VERSION 5.7 ;
  NOWIREEXTENSIONATPIN ON ;
  DIVIDERCHAR "/" ;
  BUSBITCHARS "[]" ;
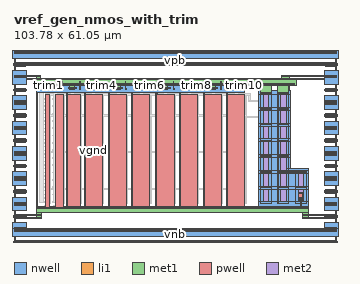
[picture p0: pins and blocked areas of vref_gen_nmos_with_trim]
MACRO vref_gen_nmos_with_trim
  CLASS BLOCK ;
  FOREIGN vref_gen_nmos_with_trim ;
  ORIGIN 0.000 0.000 ;
  SIZE 103.780 BY 61.050 ;
  PIN vpb
    ANTENNADIFFAREA 17.642599 ;
    PORT
      LAYER nwell ;
        RECT -0.330 58.865 104.110 61.465 ;
      LAYER li1 ;
        RECT 0.000 60.965 103.780 61.135 ;
      LAYER met1 ;
        RECT 0.000 60.935 103.780 61.165 ;
    END
    PORT
      LAYER nwell ;
        RECT 99.610 50.725 104.110 55.095 ;
      LAYER li1 ;
        RECT 99.940 52.825 103.780 52.995 ;
      LAYER met1 ;
        RECT 99.940 52.795 103.780 53.025 ;
    END
    PORT
      LAYER nwell ;
        RECT 99.610 42.585 104.110 46.955 ;
      LAYER li1 ;
        RECT 99.940 44.685 103.780 44.855 ;
      LAYER met1 ;
        RECT 99.940 44.655 103.780 44.885 ;
    END
    PORT
      LAYER nwell ;
        RECT 99.610 34.445 104.110 38.815 ;
      LAYER li1 ;
        RECT 99.940 36.545 103.780 36.715 ;
      LAYER met1 ;
        RECT 99.940 36.515 103.780 36.745 ;
    END
    PORT
      LAYER nwell ;
        RECT -0.330 50.725 4.170 55.095 ;
      LAYER li1 ;
        RECT 0.000 52.825 3.840 52.995 ;
      LAYER met1 ;
        RECT 0.000 52.795 3.840 53.025 ;
    END
    PORT
      LAYER nwell ;
        RECT -0.330 42.585 4.170 46.955 ;
      LAYER li1 ;
        RECT 0.000 44.685 3.840 44.855 ;
      LAYER met1 ;
        RECT 0.000 44.655 3.840 44.885 ;
    END
    PORT
      LAYER nwell ;
        RECT -0.330 34.445 4.170 38.815 ;
      LAYER li1 ;
        RECT 0.000 36.545 3.840 36.715 ;
      LAYER met1 ;
        RECT 0.000 36.515 3.840 36.745 ;
    END
    PORT
      LAYER nwell ;
        RECT -0.330 26.305 4.170 30.675 ;
      LAYER li1 ;
        RECT 0.000 28.405 3.840 28.575 ;
      LAYER met1 ;
        RECT 0.000 28.375 3.840 28.605 ;
    END
    PORT
      LAYER nwell ;
        RECT -0.330 18.165 4.170 22.535 ;
      LAYER li1 ;
        RECT 0.000 20.265 3.840 20.435 ;
      LAYER met1 ;
        RECT 0.000 20.235 3.840 20.465 ;
    END
    PORT
      LAYER nwell ;
        RECT -0.330 4.485 4.170 6.255 ;
        RECT 99.610 4.485 104.110 6.255 ;
        RECT -0.330 1.885 104.110 4.485 ;
      LAYER li1 ;
        RECT 0.000 3.985 103.780 4.155 ;
      LAYER met1 ;
        RECT 0.000 3.955 103.780 4.185 ;
    END
    PORT
      LAYER nwell ;
        RECT -0.330 10.025 4.170 14.395 ;
      LAYER li1 ;
        RECT 0.000 12.125 3.840 12.295 ;
      LAYER met1 ;
        RECT 0.000 12.095 3.840 12.325 ;
    END
    PORT
      LAYER nwell ;
        RECT 99.610 18.165 104.110 22.535 ;
      LAYER li1 ;
        RECT 99.940 20.265 103.780 20.435 ;
      LAYER met1 ;
        RECT 99.940 20.235 103.780 20.465 ;
    END
    PORT
      LAYER nwell ;
        RECT 99.610 26.305 104.110 30.675 ;
      LAYER li1 ;
        RECT 99.940 28.405 103.780 28.575 ;
      LAYER met1 ;
        RECT 99.940 28.375 103.780 28.605 ;
    END
    PORT
      LAYER nwell ;
        RECT 99.610 10.025 104.110 14.395 ;
      LAYER li1 ;
        RECT 99.940 12.125 103.780 12.295 ;
      LAYER met1 ;
        RECT 99.940 12.095 103.780 12.325 ;
    END
  END vpb
  PIN vnb
    ANTENNADIFFAREA 0.652800 ;
    PORT
      LAYER pwell ;
        RECT 99.810 48.625 103.910 49.055 ;
      LAYER li1 ;
        RECT 99.940 48.755 103.780 48.925 ;
      LAYER met1 ;
        RECT 99.940 48.725 103.780 48.955 ;
    END
    PORT
      LAYER pwell ;
        RECT -0.130 56.765 103.910 57.195 ;
      LAYER li1 ;
        RECT 0.000 56.895 103.780 57.065 ;
      LAYER met1 ;
        RECT 0.000 56.865 103.780 57.095 ;
    END
    PORT
      LAYER pwell ;
        RECT 99.810 32.345 103.910 32.775 ;
      LAYER li1 ;
        RECT 99.940 32.475 103.780 32.645 ;
      LAYER met1 ;
        RECT 99.940 32.445 103.780 32.675 ;
    END
    PORT
      LAYER pwell ;
        RECT 99.810 40.485 103.910 40.915 ;
      LAYER li1 ;
        RECT 99.940 40.615 103.780 40.785 ;
      LAYER met1 ;
        RECT 99.940 40.585 103.780 40.815 ;
    END
    PORT
      LAYER pwell ;
        RECT -0.130 48.625 3.970 49.055 ;
      LAYER li1 ;
        RECT 0.000 48.755 3.840 48.925 ;
      LAYER met1 ;
        RECT 0.000 48.725 3.840 48.955 ;
    END
    PORT
      LAYER pwell ;
        RECT -0.130 40.485 3.970 40.915 ;
      LAYER li1 ;
        RECT 0.000 40.615 3.840 40.785 ;
      LAYER met1 ;
        RECT 0.000 40.585 3.840 40.815 ;
    END
    PORT
      LAYER pwell ;
        RECT -0.130 32.345 3.970 32.775 ;
      LAYER li1 ;
        RECT 0.000 32.475 3.840 32.645 ;
      LAYER met1 ;
        RECT 0.000 32.445 3.840 32.675 ;
    END
    PORT
      LAYER pwell ;
        RECT -0.130 24.205 3.970 24.635 ;
      LAYER li1 ;
        RECT 0.000 24.335 3.840 24.505 ;
      LAYER met1 ;
        RECT 0.000 24.305 3.840 24.535 ;
    END
    PORT
      LAYER pwell ;
        RECT -0.130 16.065 3.970 16.495 ;
      LAYER li1 ;
        RECT 0.000 16.195 3.840 16.365 ;
      LAYER met1 ;
        RECT 0.000 16.165 3.840 16.395 ;
    END
    PORT
      LAYER pwell ;
        RECT -0.130 -0.215 103.910 0.215 ;
      LAYER li1 ;
        RECT 0.000 -0.085 103.780 0.085 ;
      LAYER met1 ;
        RECT 0.000 -0.115 103.780 0.115 ;
    END
    PORT
      LAYER pwell ;
        RECT -0.130 7.925 3.970 8.355 ;
      LAYER li1 ;
        RECT 0.000 8.055 3.840 8.225 ;
      LAYER met1 ;
        RECT 0.000 8.025 3.840 8.255 ;
    END
    PORT
      LAYER pwell ;
        RECT 99.810 24.205 103.910 24.635 ;
      LAYER li1 ;
        RECT 99.940 24.335 103.780 24.505 ;
      LAYER met1 ;
        RECT 99.940 24.305 103.780 24.535 ;
    END
    PORT
      LAYER pwell ;
        RECT 99.810 16.065 103.910 16.495 ;
      LAYER li1 ;
        RECT 99.940 16.195 103.780 16.365 ;
      LAYER met1 ;
        RECT 99.940 16.165 103.780 16.395 ;
    END
    PORT
      LAYER pwell ;
        RECT 99.810 7.925 103.910 8.355 ;
      LAYER li1 ;
        RECT 99.940 8.055 103.780 8.225 ;
      LAYER met1 ;
        RECT 99.940 8.025 103.780 8.255 ;
    END
  END vnb
  PIN vpwr
    PORT
      LAYER met1 ;
        RECT 0.000 60.425 103.780 60.795 ;
    END
    PORT
      LAYER nwell ;
        RECT 7.180 48.170 74.045 51.165 ;
        RECT 78.610 47.355 88.880 48.785 ;
        RECT 78.610 43.250 80.040 47.355 ;
        RECT 81.900 43.250 85.590 47.355 ;
        RECT 87.450 43.250 88.880 47.355 ;
        RECT 78.610 42.300 88.880 43.250 ;
        RECT 78.610 38.195 80.040 42.300 ;
        RECT 81.900 38.195 85.590 42.300 ;
        RECT 87.450 38.195 88.880 42.300 ;
        RECT 78.610 37.245 88.880 38.195 ;
        RECT 78.610 33.140 80.040 37.245 ;
        RECT 81.900 33.140 85.590 37.245 ;
        RECT 87.450 33.140 88.880 37.245 ;
        RECT 78.610 32.190 88.880 33.140 ;
        RECT 78.610 28.085 80.040 32.190 ;
        RECT 81.900 28.085 85.590 32.190 ;
        RECT 87.450 28.085 88.880 32.190 ;
        RECT 78.610 27.135 88.880 28.085 ;
        RECT 78.610 23.030 80.040 27.135 ;
        RECT 81.900 23.030 85.590 27.135 ;
        RECT 87.450 23.510 88.880 27.135 ;
        RECT 87.450 23.030 94.550 23.510 ;
        RECT 78.610 22.080 94.550 23.030 ;
        RECT 78.610 17.975 80.040 22.080 ;
        RECT 81.900 17.975 85.590 22.080 ;
        RECT 87.450 17.975 91.260 22.080 ;
        RECT 93.120 17.975 94.550 22.080 ;
        RECT 78.610 17.025 94.550 17.975 ;
        RECT 78.610 12.920 80.040 17.025 ;
        RECT 81.900 12.920 85.590 17.025 ;
        RECT 87.450 12.920 91.260 17.025 ;
        RECT 93.120 12.920 94.550 17.025 ;
        RECT 78.610 11.490 94.550 12.920 ;
      LAYER li1 ;
        RECT 7.700 50.465 90.045 50.795 ;
        RECT 7.490 49.430 10.200 49.600 ;
        RECT 11.975 49.430 14.685 49.600 ;
        RECT 17.435 49.430 20.145 49.600 ;
        RECT 24.460 49.430 27.170 49.600 ;
        RECT 32.195 49.430 34.905 49.600 ;
        RECT 39.750 49.430 42.460 49.600 ;
        RECT 47.560 49.430 50.270 49.600 ;
        RECT 55.070 49.430 57.780 49.600 ;
        RECT 62.745 49.430 65.455 49.600 ;
        RECT 70.255 49.430 72.965 49.600 ;
        RECT 79.135 47.745 82.795 47.915 ;
        RECT 79.135 42.860 79.305 47.745 ;
        RECT 82.625 42.860 82.795 47.745 ;
        RECT 79.135 42.690 82.795 42.860 ;
        RECT 79.135 37.805 79.305 42.690 ;
        RECT 82.625 37.805 82.795 42.690 ;
        RECT 79.135 37.635 82.795 37.805 ;
        RECT 79.135 32.750 79.305 37.635 ;
        RECT 82.625 32.750 82.795 37.635 ;
        RECT 79.135 32.580 82.795 32.750 ;
        RECT 79.135 27.695 79.305 32.580 ;
        RECT 82.625 27.695 82.795 32.580 ;
        RECT 79.135 27.525 82.795 27.695 ;
        RECT 79.135 22.640 79.305 27.525 ;
        RECT 82.625 22.640 82.795 27.525 ;
        RECT 79.135 22.470 82.795 22.640 ;
        RECT 79.135 17.585 79.305 22.470 ;
        RECT 82.625 17.585 82.795 22.470 ;
        RECT 79.135 17.415 82.795 17.585 ;
        RECT 79.135 12.505 79.305 17.415 ;
        RECT 82.625 12.505 82.795 17.415 ;
        RECT 79.135 12.335 82.795 12.505 ;
        RECT 84.685 47.745 88.345 47.915 ;
        RECT 84.685 42.860 84.855 47.745 ;
        RECT 88.175 42.860 88.345 47.745 ;
        RECT 84.685 42.690 88.345 42.860 ;
        RECT 84.685 37.805 84.855 42.690 ;
        RECT 88.175 37.805 88.345 42.690 ;
        RECT 84.685 37.635 88.345 37.805 ;
        RECT 84.685 32.750 84.855 37.635 ;
        RECT 88.175 32.750 88.345 37.635 ;
        RECT 84.685 32.580 88.345 32.750 ;
        RECT 84.685 27.695 84.855 32.580 ;
        RECT 88.175 27.695 88.345 32.580 ;
        RECT 84.685 27.525 88.345 27.695 ;
        RECT 84.685 22.640 84.855 27.525 ;
        RECT 88.175 22.640 88.345 27.525 ;
        RECT 84.685 22.470 94.015 22.640 ;
        RECT 84.685 17.585 84.855 22.470 ;
        RECT 88.175 17.585 88.345 22.470 ;
        RECT 84.685 17.415 88.345 17.585 ;
        RECT 84.685 12.505 84.855 17.415 ;
        RECT 88.175 12.505 88.345 17.415 ;
        RECT 84.685 12.335 88.345 12.505 ;
        RECT 90.355 17.585 90.525 22.470 ;
        RECT 93.845 17.585 94.015 22.470 ;
        RECT 90.355 17.415 94.015 17.585 ;
        RECT 90.355 12.505 90.525 17.415 ;
        RECT 93.845 12.505 94.015 17.415 ;
        RECT 90.355 12.335 94.015 12.505 ;
      LAYER met1 ;
        RECT 0.000 53.165 8.370 53.535 ;
        RECT 7.180 52.655 8.370 53.165 ;
        RECT 86.065 53.165 103.780 53.535 ;
        RECT 86.065 52.655 88.435 53.165 ;
        RECT 0.000 52.285 103.780 52.655 ;
        RECT 7.180 50.295 90.730 52.285 ;
        RECT 8.030 48.965 9.400 50.295 ;
        RECT 12.520 48.965 13.890 50.295 ;
        RECT 17.980 48.965 19.350 50.295 ;
        RECT 25.005 48.965 26.375 50.295 ;
        RECT 32.740 48.965 34.110 50.295 ;
        RECT 40.295 48.965 41.665 50.295 ;
        RECT 48.105 48.965 49.475 50.295 ;
        RECT 55.615 48.965 56.985 50.295 ;
        RECT 63.290 48.965 64.660 50.295 ;
        RECT 70.800 48.965 72.170 50.295 ;
        RECT 79.265 47.715 82.795 50.295 ;
        RECT 84.815 47.715 88.345 50.295 ;
        RECT 90.475 22.670 93.675 22.700 ;
        RECT 90.335 22.440 93.865 22.670 ;
      LAYER met2 ;
        RECT 79.080 12.280 82.830 51.015 ;
        RECT 84.630 12.280 88.380 51.015 ;
        RECT 90.300 12.280 94.050 23.395 ;
    END
    PORT
      LAYER met1 ;
        RECT 99.940 44.145 103.780 44.515 ;
    END
    PORT
      LAYER met1 ;
        RECT 99.940 36.005 103.780 36.375 ;
    END
    PORT
      LAYER met1 ;
        RECT 99.940 36.885 103.780 37.255 ;
    END
    PORT
      LAYER met1 ;
        RECT 99.940 45.025 103.780 45.395 ;
    END
    PORT
      LAYER met1 ;
        RECT 0.000 44.145 3.840 44.515 ;
    END
    PORT
      LAYER met1 ;
        RECT 0.000 36.005 3.840 36.375 ;
    END
    PORT
      LAYER met1 ;
        RECT 0.000 45.025 3.840 45.395 ;
    END
    PORT
      LAYER met1 ;
        RECT 0.000 36.885 3.840 37.255 ;
    END
    PORT
      LAYER met1 ;
        RECT 0.000 27.865 3.840 28.235 ;
    END
    PORT
      LAYER met1 ;
        RECT 0.000 19.725 3.840 20.095 ;
    END
    PORT
      LAYER met1 ;
        RECT 0.000 28.745 3.840 29.115 ;
    END
    PORT
      LAYER met1 ;
        RECT 0.000 20.605 3.840 20.975 ;
    END
    PORT
      LAYER met1 ;
        RECT 0.000 3.445 103.780 3.815 ;
    END
    PORT
      LAYER met1 ;
        RECT 0.000 4.325 3.840 4.695 ;
    END
    PORT
      LAYER met1 ;
        RECT 0.000 11.585 3.840 11.955 ;
    END
    PORT
      LAYER met1 ;
        RECT 0.000 12.465 3.840 12.835 ;
    END
    PORT
      LAYER met1 ;
        RECT 99.940 20.605 103.780 20.975 ;
    END
    PORT
      LAYER met1 ;
        RECT 99.940 19.725 103.780 20.095 ;
    END
    PORT
      LAYER met1 ;
        RECT 99.940 28.745 103.780 29.115 ;
    END
    PORT
      LAYER met1 ;
        RECT 99.940 27.865 103.780 28.235 ;
    END
    PORT
      LAYER met1 ;
        RECT 99.940 11.585 103.780 11.955 ;
    END
    PORT
      LAYER met1 ;
        RECT 99.940 12.465 103.780 12.835 ;
    END
    PORT
      LAYER met1 ;
        RECT 99.940 4.325 103.780 4.695 ;
    END
  END vpwr
  PIN vgnd
    PORT
      LAYER met1 ;
        RECT 99.940 48.215 103.780 48.585 ;
    END
    PORT
      LAYER met1 ;
        RECT 0.000 57.235 103.780 57.605 ;
    END
    PORT
      LAYER met1 ;
        RECT 99.940 49.095 103.780 49.465 ;
    END
    PORT
      LAYER met1 ;
        RECT 99.940 56.355 103.780 56.725 ;
    END
    PORT
      LAYER met1 ;
        RECT 99.940 31.935 103.780 32.305 ;
    END
    PORT
      LAYER met1 ;
        RECT 99.940 40.955 103.780 41.325 ;
    END
    PORT
      LAYER met1 ;
        RECT 99.940 32.815 103.780 33.185 ;
    END
    PORT
      LAYER met1 ;
        RECT 99.940 40.075 103.780 40.445 ;
    END
    PORT
      LAYER met1 ;
        RECT 0.000 56.355 3.840 56.725 ;
    END
    PORT
      LAYER met1 ;
        RECT 0.000 49.095 3.840 49.465 ;
    END
    PORT
      LAYER met1 ;
        RECT 0.000 48.215 3.840 48.585 ;
    END
    PORT
      LAYER met1 ;
        RECT 0.000 40.075 3.840 40.445 ;
    END
    PORT
      LAYER met1 ;
        RECT 0.000 40.955 3.840 41.325 ;
    END
    PORT
      LAYER met1 ;
        RECT 0.000 32.815 3.840 33.185 ;
    END
    PORT
      LAYER met1 ;
        RECT 0.000 31.935 3.840 32.305 ;
    END
    PORT
      LAYER met1 ;
        RECT 0.000 23.795 3.840 24.165 ;
    END
    PORT
      LAYER met1 ;
        RECT 0.000 24.675 3.840 25.045 ;
    END
    PORT
      LAYER met1 ;
        RECT 0.000 16.535 3.840 16.905 ;
    END
    PORT
      LAYER met1 ;
        RECT 0.000 15.655 3.840 16.025 ;
    END
    PORT
      LAYER met1 ;
        RECT 0.000 0.255 103.780 0.625 ;
    END
    PORT
      LAYER pwell ;
        RECT 7.175 11.115 7.605 47.580 ;
        RECT 16.790 47.410 17.220 47.580 ;
        RECT 22.515 47.410 22.945 47.580 ;
        RECT 30.250 47.410 30.680 47.580 ;
        RECT 37.805 47.410 38.235 47.580 ;
        RECT 45.615 47.410 46.045 47.580 ;
        RECT 53.125 47.410 53.555 47.580 ;
        RECT 60.800 47.410 61.230 47.580 ;
        RECT 68.310 47.410 68.740 47.580 ;
        RECT 10.160 11.115 11.420 47.410 ;
        RECT 13.345 11.115 15.905 47.410 ;
        RECT 16.790 11.115 21.365 47.410 ;
        RECT 22.515 11.115 28.390 47.410 ;
        RECT 30.250 11.115 36.125 47.410 ;
        RECT 37.805 11.115 43.680 47.410 ;
        RECT 45.615 11.115 51.490 47.410 ;
        RECT 53.125 11.115 59.000 47.410 ;
        RECT 60.800 11.115 66.675 47.410 ;
        RECT 68.310 11.115 74.185 47.410 ;
        RECT 91.560 13.220 92.820 16.005 ;
        RECT 7.170 10.685 94.330 11.115 ;
      LAYER li1 ;
        RECT 7.305 11.065 7.475 47.410 ;
        RECT 16.920 11.065 17.090 47.410 ;
        RECT 22.645 11.065 22.815 47.410 ;
        RECT 30.380 11.065 30.550 47.410 ;
        RECT 37.935 11.065 38.105 47.410 ;
        RECT 45.745 11.065 45.915 47.410 ;
        RECT 53.255 11.065 53.425 47.410 ;
        RECT 60.930 11.065 61.100 47.410 ;
        RECT 68.440 11.065 68.610 47.410 ;
        RECT 91.700 15.665 93.120 15.835 ;
        RECT 92.950 14.275 93.120 15.665 ;
        RECT 91.700 14.105 93.120 14.275 ;
        RECT 92.095 13.600 92.265 14.105 ;
        RECT 91.465 13.270 92.995 13.600 ;
        RECT 7.305 10.985 94.325 11.065 ;
        RECT 7.305 10.815 94.385 10.985 ;
        RECT 7.305 10.735 94.325 10.815 ;
      LAYER met1 ;
        RECT 92.065 13.290 92.355 13.580 ;
        RECT 92.140 11.280 92.280 13.290 ;
        RECT 7.180 9.550 94.590 11.280 ;
        RECT 7.180 8.765 8.920 9.550 ;
        RECT 0.000 8.395 8.920 8.765 ;
        RECT 7.180 7.885 8.920 8.395 ;
        RECT 0.000 7.515 8.920 7.885 ;
        RECT 92.850 8.765 94.590 9.550 ;
        RECT 92.850 8.395 103.780 8.765 ;
        RECT 92.850 7.885 94.590 8.395 ;
        RECT 92.850 7.515 103.780 7.885 ;
    END
    PORT
      LAYER met1 ;
        RECT 99.940 24.675 103.780 25.045 ;
    END
    PORT
      LAYER met1 ;
        RECT 99.940 23.795 103.780 24.165 ;
    END
    PORT
      LAYER met1 ;
        RECT 99.940 16.535 103.780 16.905 ;
    END
    PORT
      LAYER met1 ;
        RECT 99.940 15.655 103.780 16.025 ;
    END
  END vgnd
  PIN trim9
    ANTENNAGATEAREA 1.500000 ;
    PORT
      LAYER li1 ;
        RECT 66.300 48.980 66.630 49.310 ;
      LAYER met1 ;
        RECT 66.320 49.275 66.610 49.290 ;
        RECT 66.300 49.015 66.620 49.275 ;
        RECT 66.320 49.000 66.610 49.015 ;
      LAYER met2 ;
        RECT 66.395 49.275 66.535 51.560 ;
        RECT 66.300 49.015 66.620 49.275 ;
    END
  END trim9
  PIN trim10
    ANTENNAGATEAREA 1.500000 ;
    PORT
      LAYER li1 ;
        RECT 73.810 48.980 74.140 49.310 ;
      LAYER met1 ;
        RECT 73.830 49.275 74.120 49.290 ;
        RECT 73.810 49.015 74.130 49.275 ;
        RECT 73.830 49.000 74.120 49.015 ;
      LAYER met2 ;
        RECT 73.905 49.275 74.045 51.560 ;
        RECT 73.810 49.015 74.130 49.275 ;
    END
  END trim10
  PIN trim8
    ANTENNAGATEAREA 1.500000 ;
    PORT
      LAYER li1 ;
        RECT 58.625 48.980 58.955 49.310 ;
      LAYER met1 ;
        RECT 58.645 49.275 58.935 49.290 ;
        RECT 58.625 49.015 58.945 49.275 ;
        RECT 58.645 49.000 58.935 49.015 ;
      LAYER met2 ;
        RECT 58.720 49.275 58.860 51.560 ;
        RECT 58.625 49.015 58.945 49.275 ;
    END
  END trim8
  PIN trim7
    ANTENNAGATEAREA 1.500000 ;
    PORT
      LAYER li1 ;
        RECT 51.115 48.980 51.445 49.310 ;
      LAYER met1 ;
        RECT 51.135 49.275 51.425 49.290 ;
        RECT 51.115 49.015 51.435 49.275 ;
        RECT 51.135 49.000 51.425 49.015 ;
      LAYER met2 ;
        RECT 51.210 49.275 51.350 51.560 ;
        RECT 51.115 49.015 51.435 49.275 ;
    END
  END trim7
  PIN trim6
    ANTENNAGATEAREA 1.500000 ;
    PORT
      LAYER li1 ;
        RECT 43.305 48.980 43.635 49.310 ;
      LAYER met1 ;
        RECT 43.325 49.275 43.615 49.290 ;
        RECT 43.305 49.015 43.625 49.275 ;
        RECT 43.325 49.000 43.615 49.015 ;
      LAYER met2 ;
        RECT 43.400 49.275 43.540 51.560 ;
        RECT 43.305 49.015 43.625 49.275 ;
    END
  END trim6
  PIN trim5
    ANTENNAGATEAREA 1.500000 ;
    PORT
      LAYER li1 ;
        RECT 35.750 48.980 36.080 49.310 ;
      LAYER met1 ;
        RECT 35.770 49.275 36.060 49.290 ;
        RECT 35.750 49.015 36.070 49.275 ;
        RECT 35.770 49.000 36.060 49.015 ;
      LAYER met2 ;
        RECT 35.845 49.275 35.985 51.560 ;
        RECT 35.750 49.015 36.070 49.275 ;
    END
  END trim5
  PIN trim4
    ANTENNAGATEAREA 1.500000 ;
    PORT
      LAYER li1 ;
        RECT 28.015 48.980 28.345 49.310 ;
      LAYER met1 ;
        RECT 28.035 49.275 28.325 49.290 ;
        RECT 28.015 49.015 28.335 49.275 ;
        RECT 28.035 49.000 28.325 49.015 ;
      LAYER met2 ;
        RECT 28.110 49.275 28.250 51.560 ;
        RECT 28.015 49.015 28.335 49.275 ;
    END
  END trim4
  PIN trim3
    ANTENNAGATEAREA 1.500000 ;
    PORT
      LAYER li1 ;
        RECT 21.025 48.980 21.355 49.310 ;
      LAYER met1 ;
        RECT 21.045 49.275 21.335 49.290 ;
        RECT 21.025 49.015 21.345 49.275 ;
        RECT 21.045 49.000 21.335 49.015 ;
      LAYER met2 ;
        RECT 21.115 49.275 21.255 51.560 ;
        RECT 21.025 49.015 21.345 49.275 ;
    END
  END trim3
  PIN trim2
    ANTENNAGATEAREA 1.500000 ;
    PORT
      LAYER li1 ;
        RECT 15.500 48.980 15.830 49.310 ;
      LAYER met1 ;
        RECT 15.520 49.275 15.810 49.290 ;
        RECT 15.500 49.015 15.820 49.275 ;
        RECT 15.520 49.000 15.810 49.015 ;
      LAYER met2 ;
        RECT 15.595 49.275 15.735 51.560 ;
        RECT 15.500 49.015 15.820 49.275 ;
    END
  END trim2
  PIN trim1
    ANTENNAGATEAREA 1.500000 ;
    PORT
      LAYER li1 ;
        RECT 10.895 48.980 11.225 49.310 ;
      LAYER met1 ;
        RECT 10.915 49.275 11.205 49.290 ;
        RECT 10.895 49.015 11.215 49.275 ;
        RECT 10.915 49.000 11.205 49.015 ;
      LAYER met2 ;
        RECT 10.980 49.275 11.120 51.560 ;
        RECT 10.895 49.015 11.215 49.275 ;
    END
  END trim1
  OBS
      LAYER pwell ;
        RECT 80.340 43.550 81.600 46.335 ;
        RECT 85.890 43.550 87.150 46.335 ;
        RECT 80.340 38.495 81.600 41.280 ;
        RECT 85.890 38.495 87.150 41.280 ;
        RECT 80.340 33.440 81.600 36.225 ;
        RECT 85.890 33.440 87.150 36.225 ;
        RECT 80.340 28.385 81.600 31.170 ;
        RECT 85.890 28.385 87.150 31.170 ;
        RECT 80.340 23.330 81.600 26.115 ;
        RECT 85.890 23.330 87.150 26.115 ;
        RECT 80.340 18.275 81.600 21.060 ;
        RECT 85.890 18.275 87.150 21.060 ;
        RECT 91.560 18.275 92.820 21.060 ;
        RECT 80.340 13.220 81.600 16.005 ;
        RECT 85.890 13.220 87.150 16.005 ;
      LAYER li1 ;
        RECT 7.490 48.650 10.200 48.820 ;
        RECT 11.975 48.650 14.685 48.820 ;
        RECT 17.435 48.650 20.145 48.820 ;
        RECT 24.460 48.650 27.170 48.820 ;
        RECT 32.195 48.650 34.905 48.820 ;
        RECT 39.750 48.650 42.460 48.820 ;
        RECT 47.560 48.650 50.270 48.820 ;
        RECT 55.070 48.650 57.780 48.820 ;
        RECT 62.745 48.650 65.455 48.820 ;
        RECT 70.255 48.650 72.965 48.820 ;
        RECT 7.965 48.545 9.510 48.650 ;
        RECT 12.480 48.525 13.890 48.650 ;
        RECT 17.980 48.525 19.350 48.650 ;
        RECT 25.005 48.500 26.375 48.650 ;
        RECT 32.740 48.500 34.110 48.650 ;
        RECT 40.295 48.500 41.665 48.650 ;
        RECT 48.105 48.500 49.475 48.650 ;
        RECT 55.615 48.500 56.985 48.650 ;
        RECT 63.290 48.500 64.660 48.650 ;
        RECT 70.800 48.500 72.170 48.650 ;
        RECT 10.105 47.070 11.315 47.580 ;
        RECT 13.475 47.410 15.795 47.580 ;
        RECT 17.600 47.410 21.255 47.580 ;
        RECT 13.475 47.240 15.800 47.410 ;
        RECT 17.600 47.240 21.260 47.410 ;
        RECT 13.485 47.070 15.795 47.240 ;
        RECT 17.600 47.070 21.255 47.240 ;
        RECT 23.185 47.070 29.425 47.580 ;
        RECT 30.920 47.070 37.160 47.580 ;
        RECT 38.475 47.070 44.715 47.580 ;
        RECT 46.285 47.070 52.525 47.580 ;
        RECT 53.795 47.070 60.035 47.580 ;
        RECT 61.470 47.070 67.710 47.580 ;
        RECT 68.980 47.070 75.220 47.580 ;
        RECT 11.525 46.295 11.855 46.625 ;
        RECT 16.010 46.295 16.340 46.625 ;
        RECT 21.470 46.295 21.800 46.625 ;
        RECT 28.495 46.295 28.825 46.625 ;
        RECT 36.230 46.295 36.560 46.625 ;
        RECT 43.785 46.295 44.115 46.625 ;
        RECT 51.595 46.295 51.925 46.625 ;
        RECT 59.105 46.295 59.435 46.625 ;
        RECT 66.780 46.295 67.110 46.625 ;
        RECT 74.290 46.295 74.620 46.625 ;
        RECT 8.045 45.890 11.310 46.060 ;
        RECT 12.530 45.890 15.795 46.060 ;
        RECT 17.645 45.890 21.255 46.060 ;
        RECT 23.360 45.890 28.280 46.060 ;
        RECT 31.095 45.890 36.015 46.060 ;
        RECT 38.650 45.890 43.570 46.060 ;
        RECT 46.460 45.890 51.380 46.060 ;
        RECT 53.970 45.890 58.890 46.060 ;
        RECT 61.645 45.890 66.565 46.060 ;
        RECT 69.155 45.890 74.075 46.060 ;
        RECT 80.480 45.995 81.900 46.165 ;
        RECT 86.030 45.995 87.450 46.165 ;
        RECT 8.095 45.885 9.345 45.890 ;
        RECT 12.580 45.885 13.830 45.890 ;
        RECT 18.040 45.885 19.290 45.890 ;
        RECT 25.065 45.885 26.315 45.890 ;
        RECT 32.800 45.885 34.050 45.890 ;
        RECT 40.355 45.885 41.605 45.890 ;
        RECT 48.165 45.885 49.415 45.890 ;
        RECT 55.675 45.885 56.925 45.890 ;
        RECT 63.350 45.885 64.600 45.890 ;
        RECT 70.860 45.885 72.110 45.890 ;
        RECT 11.525 45.245 11.855 45.575 ;
        RECT 16.010 45.245 16.340 45.575 ;
        RECT 21.470 45.245 21.800 45.575 ;
        RECT 28.495 45.245 28.825 45.575 ;
        RECT 36.230 45.245 36.560 45.575 ;
        RECT 43.785 45.245 44.115 45.575 ;
        RECT 51.595 45.245 51.925 45.575 ;
        RECT 59.105 45.245 59.435 45.575 ;
        RECT 66.780 45.245 67.110 45.575 ;
        RECT 74.290 45.245 74.620 45.575 ;
        RECT 80.015 45.385 80.345 45.465 ;
        RECT 80.015 45.215 81.490 45.385 ;
        RECT 80.015 45.135 80.345 45.215 ;
        RECT 9.825 44.710 11.310 44.880 ;
        RECT 12.560 44.710 15.795 44.880 ;
        RECT 17.600 44.710 21.255 44.880 ;
        RECT 23.185 44.710 28.280 44.880 ;
        RECT 30.920 44.710 36.015 44.880 ;
        RECT 38.475 44.710 43.570 44.880 ;
        RECT 46.285 44.710 51.380 44.880 ;
        RECT 53.795 44.710 58.890 44.880 ;
        RECT 61.470 44.710 66.565 44.880 ;
        RECT 68.980 44.710 74.075 44.880 ;
        RECT 81.730 44.605 81.900 45.995 ;
        RECT 85.565 45.385 85.895 45.465 ;
        RECT 85.565 45.215 87.040 45.385 ;
        RECT 85.565 45.135 85.895 45.215 ;
        RECT 87.280 44.605 87.450 45.995 ;
        RECT 80.480 44.435 81.900 44.605 ;
        RECT 86.030 44.435 87.450 44.605 ;
        RECT 11.525 44.020 11.855 44.350 ;
        RECT 16.010 44.020 16.340 44.350 ;
        RECT 21.470 44.020 21.800 44.350 ;
        RECT 28.495 44.020 28.825 44.350 ;
        RECT 36.230 44.020 36.560 44.350 ;
        RECT 43.785 44.020 44.115 44.350 ;
        RECT 51.595 44.020 51.925 44.350 ;
        RECT 59.105 44.020 59.435 44.350 ;
        RECT 66.780 44.020 67.110 44.350 ;
        RECT 74.290 44.020 74.620 44.350 ;
        RECT 80.875 43.930 81.045 44.435 ;
        RECT 86.425 43.930 86.595 44.435 ;
        RECT 8.045 43.530 11.310 43.700 ;
        RECT 12.530 43.530 15.795 43.700 ;
        RECT 17.645 43.530 21.255 43.700 ;
        RECT 23.360 43.530 28.280 43.700 ;
        RECT 31.095 43.530 36.015 43.700 ;
        RECT 38.650 43.530 43.570 43.700 ;
        RECT 46.460 43.530 51.380 43.700 ;
        RECT 53.970 43.530 58.890 43.700 ;
        RECT 61.645 43.530 66.565 43.700 ;
        RECT 69.155 43.530 74.075 43.700 ;
        RECT 80.245 43.600 81.775 43.930 ;
        RECT 85.795 43.600 87.325 43.930 ;
        RECT 8.095 43.525 9.345 43.530 ;
        RECT 12.580 43.525 13.830 43.530 ;
        RECT 18.040 43.525 19.290 43.530 ;
        RECT 25.065 43.525 26.315 43.530 ;
        RECT 32.800 43.525 34.050 43.530 ;
        RECT 40.355 43.525 41.605 43.530 ;
        RECT 48.165 43.525 49.415 43.530 ;
        RECT 55.675 43.525 56.925 43.530 ;
        RECT 63.350 43.525 64.600 43.530 ;
        RECT 70.860 43.525 72.110 43.530 ;
        RECT 11.525 42.910 11.855 43.240 ;
        RECT 16.010 42.910 16.340 43.240 ;
        RECT 21.470 42.910 21.800 43.240 ;
        RECT 28.495 42.910 28.825 43.240 ;
        RECT 36.230 42.910 36.560 43.240 ;
        RECT 43.785 42.910 44.115 43.240 ;
        RECT 51.595 42.910 51.925 43.240 ;
        RECT 59.105 42.910 59.435 43.240 ;
        RECT 66.780 42.910 67.110 43.240 ;
        RECT 74.290 42.910 74.620 43.240 ;
        RECT 9.825 42.350 11.310 42.520 ;
        RECT 12.560 42.350 15.795 42.520 ;
        RECT 17.600 42.350 21.255 42.520 ;
        RECT 23.185 42.350 28.280 42.520 ;
        RECT 30.920 42.350 36.015 42.520 ;
        RECT 38.475 42.350 43.570 42.520 ;
        RECT 46.285 42.350 51.380 42.520 ;
        RECT 53.795 42.350 58.890 42.520 ;
        RECT 61.470 42.350 66.565 42.520 ;
        RECT 68.980 42.350 74.075 42.520 ;
        RECT 11.525 41.725 11.855 42.055 ;
        RECT 16.010 41.725 16.340 42.055 ;
        RECT 21.470 41.725 21.800 42.055 ;
        RECT 28.495 41.725 28.825 42.055 ;
        RECT 36.230 41.725 36.560 42.055 ;
        RECT 43.785 41.725 44.115 42.055 ;
        RECT 51.595 41.725 51.925 42.055 ;
        RECT 59.105 41.725 59.435 42.055 ;
        RECT 66.780 41.725 67.110 42.055 ;
        RECT 74.290 41.725 74.620 42.055 ;
        RECT 8.045 41.170 11.310 41.340 ;
        RECT 12.530 41.170 15.795 41.340 ;
        RECT 17.645 41.170 21.255 41.340 ;
        RECT 23.360 41.170 28.280 41.340 ;
        RECT 31.095 41.170 36.015 41.340 ;
        RECT 38.650 41.170 43.570 41.340 ;
        RECT 46.460 41.170 51.380 41.340 ;
        RECT 53.970 41.170 58.890 41.340 ;
        RECT 61.645 41.170 66.565 41.340 ;
        RECT 69.155 41.170 74.075 41.340 ;
        RECT 80.480 40.940 81.900 41.110 ;
        RECT 86.030 40.940 87.450 41.110 ;
        RECT 11.525 40.545 11.855 40.875 ;
        RECT 16.010 40.545 16.340 40.875 ;
        RECT 21.470 40.545 21.800 40.875 ;
        RECT 28.495 40.545 28.825 40.875 ;
        RECT 36.230 40.545 36.560 40.875 ;
        RECT 43.785 40.545 44.115 40.875 ;
        RECT 51.595 40.545 51.925 40.875 ;
        RECT 59.105 40.545 59.435 40.875 ;
        RECT 66.780 40.545 67.110 40.875 ;
        RECT 74.290 40.545 74.620 40.875 ;
        RECT 80.015 40.330 80.345 40.410 ;
        RECT 80.015 40.160 81.490 40.330 ;
        RECT 9.825 39.990 11.310 40.160 ;
        RECT 12.560 39.990 15.795 40.160 ;
        RECT 17.600 39.990 21.255 40.160 ;
        RECT 23.185 39.990 28.280 40.160 ;
        RECT 30.920 39.990 36.015 40.160 ;
        RECT 38.475 39.990 43.570 40.160 ;
        RECT 46.285 39.990 51.380 40.160 ;
        RECT 53.795 39.990 58.890 40.160 ;
        RECT 61.470 39.990 66.565 40.160 ;
        RECT 68.980 39.990 74.075 40.160 ;
        RECT 80.015 40.080 80.345 40.160 ;
        RECT 11.525 39.305 11.855 39.635 ;
        RECT 16.010 39.305 16.340 39.635 ;
        RECT 21.470 39.305 21.800 39.635 ;
        RECT 28.495 39.305 28.825 39.635 ;
        RECT 36.230 39.305 36.560 39.635 ;
        RECT 43.785 39.305 44.115 39.635 ;
        RECT 51.595 39.305 51.925 39.635 ;
        RECT 59.105 39.305 59.435 39.635 ;
        RECT 66.780 39.305 67.110 39.635 ;
        RECT 74.290 39.305 74.620 39.635 ;
        RECT 81.730 39.550 81.900 40.940 ;
        RECT 85.565 40.330 85.895 40.410 ;
        RECT 85.565 40.160 87.040 40.330 ;
        RECT 85.565 40.080 85.895 40.160 ;
        RECT 87.280 39.550 87.450 40.940 ;
        RECT 80.480 39.380 81.900 39.550 ;
        RECT 86.030 39.380 87.450 39.550 ;
        RECT 8.045 38.810 11.310 38.980 ;
        RECT 12.530 38.810 15.795 38.980 ;
        RECT 17.645 38.810 21.255 38.980 ;
        RECT 23.360 38.810 28.280 38.980 ;
        RECT 31.095 38.810 36.015 38.980 ;
        RECT 38.650 38.810 43.570 38.980 ;
        RECT 46.460 38.810 51.380 38.980 ;
        RECT 53.970 38.810 58.890 38.980 ;
        RECT 61.645 38.810 66.565 38.980 ;
        RECT 69.155 38.810 74.075 38.980 ;
        RECT 80.875 38.875 81.045 39.380 ;
        RECT 86.425 38.875 86.595 39.380 ;
        RECT 11.525 38.255 11.855 38.585 ;
        RECT 16.010 38.255 16.340 38.585 ;
        RECT 21.470 38.255 21.800 38.585 ;
        RECT 28.495 38.255 28.825 38.585 ;
        RECT 36.230 38.255 36.560 38.585 ;
        RECT 43.785 38.255 44.115 38.585 ;
        RECT 51.595 38.255 51.925 38.585 ;
        RECT 59.105 38.255 59.435 38.585 ;
        RECT 66.780 38.255 67.110 38.585 ;
        RECT 74.290 38.255 74.620 38.585 ;
        RECT 80.245 38.545 81.775 38.875 ;
        RECT 85.795 38.545 87.325 38.875 ;
        RECT 9.825 37.630 11.310 37.800 ;
        RECT 12.560 37.630 15.795 37.800 ;
        RECT 17.600 37.630 21.255 37.800 ;
        RECT 23.185 37.630 28.280 37.800 ;
        RECT 30.920 37.630 36.015 37.800 ;
        RECT 38.475 37.630 43.570 37.800 ;
        RECT 46.285 37.630 51.380 37.800 ;
        RECT 53.795 37.630 58.890 37.800 ;
        RECT 61.470 37.630 66.565 37.800 ;
        RECT 68.980 37.630 74.075 37.800 ;
        RECT 11.525 37.030 11.855 37.360 ;
        RECT 16.010 37.030 16.340 37.360 ;
        RECT 21.470 37.030 21.800 37.360 ;
        RECT 28.495 37.030 28.825 37.360 ;
        RECT 36.230 37.030 36.560 37.360 ;
        RECT 43.785 37.030 44.115 37.360 ;
        RECT 51.595 37.030 51.925 37.360 ;
        RECT 59.105 37.030 59.435 37.360 ;
        RECT 66.780 37.030 67.110 37.360 ;
        RECT 74.290 37.030 74.620 37.360 ;
        RECT 8.045 36.450 11.310 36.620 ;
        RECT 12.530 36.450 15.795 36.620 ;
        RECT 17.645 36.450 21.255 36.620 ;
        RECT 23.360 36.450 28.280 36.620 ;
        RECT 31.095 36.450 36.015 36.620 ;
        RECT 38.650 36.450 43.570 36.620 ;
        RECT 46.460 36.450 51.380 36.620 ;
        RECT 53.970 36.450 58.890 36.620 ;
        RECT 61.645 36.450 66.565 36.620 ;
        RECT 69.155 36.450 74.075 36.620 ;
        RECT 11.525 35.920 11.855 36.250 ;
        RECT 16.010 35.920 16.340 36.250 ;
        RECT 21.470 35.920 21.800 36.250 ;
        RECT 28.495 35.920 28.825 36.250 ;
        RECT 36.230 35.920 36.560 36.250 ;
        RECT 43.785 35.920 44.115 36.250 ;
        RECT 51.595 35.920 51.925 36.250 ;
        RECT 59.105 35.920 59.435 36.250 ;
        RECT 66.780 35.920 67.110 36.250 ;
        RECT 74.290 35.920 74.620 36.250 ;
        RECT 80.480 35.885 81.900 36.055 ;
        RECT 86.030 35.885 87.450 36.055 ;
        RECT 9.825 35.270 11.310 35.440 ;
        RECT 12.560 35.270 15.795 35.440 ;
        RECT 17.600 35.270 21.255 35.440 ;
        RECT 23.185 35.270 28.280 35.440 ;
        RECT 30.920 35.270 36.015 35.440 ;
        RECT 38.475 35.270 43.570 35.440 ;
        RECT 46.285 35.270 51.380 35.440 ;
        RECT 53.795 35.270 58.890 35.440 ;
        RECT 61.470 35.270 66.565 35.440 ;
        RECT 68.980 35.270 74.075 35.440 ;
        RECT 80.015 35.275 80.345 35.355 ;
        RECT 80.015 35.105 81.490 35.275 ;
        RECT 11.525 34.735 11.855 35.065 ;
        RECT 16.010 34.735 16.340 35.065 ;
        RECT 21.470 34.735 21.800 35.065 ;
        RECT 28.495 34.735 28.825 35.065 ;
        RECT 36.230 34.735 36.560 35.065 ;
        RECT 43.785 34.735 44.115 35.065 ;
        RECT 51.595 34.735 51.925 35.065 ;
        RECT 59.105 34.735 59.435 35.065 ;
        RECT 66.780 34.735 67.110 35.065 ;
        RECT 74.290 34.735 74.620 35.065 ;
        RECT 80.015 35.025 80.345 35.105 ;
        RECT 81.730 34.495 81.900 35.885 ;
        RECT 85.565 35.275 85.895 35.355 ;
        RECT 85.565 35.105 87.040 35.275 ;
        RECT 85.565 35.025 85.895 35.105 ;
        RECT 87.280 34.495 87.450 35.885 ;
        RECT 80.480 34.325 81.900 34.495 ;
        RECT 86.030 34.325 87.450 34.495 ;
        RECT 8.045 34.090 11.310 34.260 ;
        RECT 12.530 34.090 15.795 34.260 ;
        RECT 17.645 34.090 21.255 34.260 ;
        RECT 23.360 34.090 28.280 34.260 ;
        RECT 31.095 34.090 36.015 34.260 ;
        RECT 38.650 34.090 43.570 34.260 ;
        RECT 46.460 34.090 51.380 34.260 ;
        RECT 53.970 34.090 58.890 34.260 ;
        RECT 61.645 34.090 66.565 34.260 ;
        RECT 69.155 34.090 74.075 34.260 ;
        RECT 11.525 33.555 11.855 33.885 ;
        RECT 16.010 33.555 16.340 33.885 ;
        RECT 21.470 33.555 21.800 33.885 ;
        RECT 28.495 33.555 28.825 33.885 ;
        RECT 36.230 33.555 36.560 33.885 ;
        RECT 43.785 33.555 44.115 33.885 ;
        RECT 51.595 33.555 51.925 33.885 ;
        RECT 59.105 33.555 59.435 33.885 ;
        RECT 66.780 33.555 67.110 33.885 ;
        RECT 74.290 33.555 74.620 33.885 ;
        RECT 80.875 33.820 81.045 34.325 ;
        RECT 86.425 33.820 86.595 34.325 ;
        RECT 80.245 33.490 81.775 33.820 ;
        RECT 85.795 33.490 87.325 33.820 ;
        RECT 9.825 32.910 11.310 33.080 ;
        RECT 12.560 32.910 15.795 33.080 ;
        RECT 17.600 32.910 21.255 33.080 ;
        RECT 23.185 32.910 28.280 33.080 ;
        RECT 30.920 32.910 36.015 33.080 ;
        RECT 38.475 32.910 43.570 33.080 ;
        RECT 46.285 32.910 51.380 33.080 ;
        RECT 53.795 32.910 58.890 33.080 ;
        RECT 61.470 32.910 66.565 33.080 ;
        RECT 68.980 32.910 74.075 33.080 ;
        RECT 11.525 32.280 11.855 32.610 ;
        RECT 16.010 32.280 16.340 32.610 ;
        RECT 21.470 32.280 21.800 32.610 ;
        RECT 28.495 32.280 28.825 32.610 ;
        RECT 36.230 32.280 36.560 32.610 ;
        RECT 43.785 32.280 44.115 32.610 ;
        RECT 51.595 32.280 51.925 32.610 ;
        RECT 59.105 32.280 59.435 32.610 ;
        RECT 66.780 32.280 67.110 32.610 ;
        RECT 74.290 32.280 74.620 32.610 ;
        RECT 8.045 31.730 11.310 31.900 ;
        RECT 12.530 31.730 15.795 31.900 ;
        RECT 17.645 31.730 21.255 31.900 ;
        RECT 23.360 31.730 28.280 31.900 ;
        RECT 31.095 31.730 36.015 31.900 ;
        RECT 38.650 31.730 43.570 31.900 ;
        RECT 46.460 31.730 51.380 31.900 ;
        RECT 53.970 31.730 58.890 31.900 ;
        RECT 61.645 31.730 66.565 31.900 ;
        RECT 69.155 31.730 74.075 31.900 ;
        RECT 11.525 31.230 11.855 31.560 ;
        RECT 16.010 31.230 16.340 31.560 ;
        RECT 21.470 31.230 21.800 31.560 ;
        RECT 28.495 31.230 28.825 31.560 ;
        RECT 36.230 31.230 36.560 31.560 ;
        RECT 43.785 31.230 44.115 31.560 ;
        RECT 51.595 31.230 51.925 31.560 ;
        RECT 59.105 31.230 59.435 31.560 ;
        RECT 66.780 31.230 67.110 31.560 ;
        RECT 74.290 31.230 74.620 31.560 ;
        RECT 80.480 30.830 81.900 31.000 ;
        RECT 86.030 30.830 87.450 31.000 ;
        RECT 9.825 30.550 11.310 30.720 ;
        RECT 12.560 30.550 15.795 30.720 ;
        RECT 17.600 30.550 21.255 30.720 ;
        RECT 23.185 30.550 28.280 30.720 ;
        RECT 30.920 30.550 36.015 30.720 ;
        RECT 38.475 30.550 43.570 30.720 ;
        RECT 46.285 30.550 51.380 30.720 ;
        RECT 53.795 30.550 58.890 30.720 ;
        RECT 61.470 30.550 66.565 30.720 ;
        RECT 68.980 30.550 74.075 30.720 ;
        RECT 11.525 30.005 11.855 30.335 ;
        RECT 16.010 30.005 16.340 30.335 ;
        RECT 21.470 30.005 21.800 30.335 ;
        RECT 28.495 30.005 28.825 30.335 ;
        RECT 36.230 30.005 36.560 30.335 ;
        RECT 43.785 30.005 44.115 30.335 ;
        RECT 51.595 30.005 51.925 30.335 ;
        RECT 59.105 30.005 59.435 30.335 ;
        RECT 66.780 30.005 67.110 30.335 ;
        RECT 74.290 30.005 74.620 30.335 ;
        RECT 80.015 30.220 80.345 30.300 ;
        RECT 80.015 30.050 81.490 30.220 ;
        RECT 80.015 29.970 80.345 30.050 ;
        RECT 8.045 29.370 11.310 29.540 ;
        RECT 12.530 29.370 15.795 29.540 ;
        RECT 17.645 29.370 21.255 29.540 ;
        RECT 23.360 29.370 28.280 29.540 ;
        RECT 31.095 29.370 36.015 29.540 ;
        RECT 38.650 29.370 43.570 29.540 ;
        RECT 46.460 29.370 51.380 29.540 ;
        RECT 53.970 29.370 58.890 29.540 ;
        RECT 61.645 29.370 66.565 29.540 ;
        RECT 69.155 29.370 74.075 29.540 ;
        RECT 81.730 29.440 81.900 30.830 ;
        RECT 85.565 30.220 85.895 30.300 ;
        RECT 85.565 30.050 87.040 30.220 ;
        RECT 85.565 29.970 85.895 30.050 ;
        RECT 87.280 29.440 87.450 30.830 ;
        RECT 80.480 29.270 81.900 29.440 ;
        RECT 86.030 29.270 87.450 29.440 ;
        RECT 11.525 28.895 11.855 29.225 ;
        RECT 16.010 28.895 16.340 29.225 ;
        RECT 21.470 28.895 21.800 29.225 ;
        RECT 28.495 28.895 28.825 29.225 ;
        RECT 36.230 28.895 36.560 29.225 ;
        RECT 43.785 28.895 44.115 29.225 ;
        RECT 51.595 28.895 51.925 29.225 ;
        RECT 59.105 28.895 59.435 29.225 ;
        RECT 66.780 28.895 67.110 29.225 ;
        RECT 74.290 28.895 74.620 29.225 ;
        RECT 80.875 28.765 81.045 29.270 ;
        RECT 86.425 28.765 86.595 29.270 ;
        RECT 80.245 28.435 81.775 28.765 ;
        RECT 85.795 28.435 87.325 28.765 ;
        RECT 9.825 28.190 11.310 28.360 ;
        RECT 12.560 28.190 15.795 28.360 ;
        RECT 17.600 28.190 21.255 28.360 ;
        RECT 23.185 28.190 28.280 28.360 ;
        RECT 30.920 28.190 36.015 28.360 ;
        RECT 38.475 28.190 43.570 28.360 ;
        RECT 46.285 28.190 51.380 28.360 ;
        RECT 53.795 28.190 58.890 28.360 ;
        RECT 61.470 28.190 66.565 28.360 ;
        RECT 68.980 28.190 74.075 28.360 ;
        RECT 11.525 27.710 11.855 28.040 ;
        RECT 16.010 27.710 16.340 28.040 ;
        RECT 21.470 27.710 21.800 28.040 ;
        RECT 28.495 27.710 28.825 28.040 ;
        RECT 36.230 27.710 36.560 28.040 ;
        RECT 43.785 27.710 44.115 28.040 ;
        RECT 51.595 27.710 51.925 28.040 ;
        RECT 59.105 27.710 59.435 28.040 ;
        RECT 66.780 27.710 67.110 28.040 ;
        RECT 74.290 27.710 74.620 28.040 ;
        RECT 8.045 27.010 11.310 27.180 ;
        RECT 12.530 27.010 15.795 27.180 ;
        RECT 17.645 27.010 21.255 27.180 ;
        RECT 23.360 27.010 28.280 27.180 ;
        RECT 31.095 27.010 36.015 27.180 ;
        RECT 38.650 27.010 43.570 27.180 ;
        RECT 46.460 27.010 51.380 27.180 ;
        RECT 53.970 27.010 58.890 27.180 ;
        RECT 61.645 27.010 66.565 27.180 ;
        RECT 69.155 27.010 74.075 27.180 ;
        RECT 11.525 26.530 11.855 26.860 ;
        RECT 16.010 26.530 16.340 26.860 ;
        RECT 21.470 26.530 21.800 26.860 ;
        RECT 28.495 26.530 28.825 26.860 ;
        RECT 36.230 26.530 36.560 26.860 ;
        RECT 43.785 26.530 44.115 26.860 ;
        RECT 51.595 26.530 51.925 26.860 ;
        RECT 59.105 26.530 59.435 26.860 ;
        RECT 66.780 26.530 67.110 26.860 ;
        RECT 74.290 26.530 74.620 26.860 ;
        RECT 9.825 25.830 11.310 26.000 ;
        RECT 12.560 25.830 15.795 26.000 ;
        RECT 17.600 25.830 21.255 26.000 ;
        RECT 23.185 25.830 28.280 26.000 ;
        RECT 30.920 25.830 36.015 26.000 ;
        RECT 38.475 25.830 43.570 26.000 ;
        RECT 46.285 25.830 51.380 26.000 ;
        RECT 53.795 25.830 58.890 26.000 ;
        RECT 61.470 25.830 66.565 26.000 ;
        RECT 68.980 25.830 74.075 26.000 ;
        RECT 80.480 25.775 81.900 25.945 ;
        RECT 86.030 25.775 87.450 25.945 ;
        RECT 11.525 25.175 11.855 25.505 ;
        RECT 16.010 25.175 16.340 25.505 ;
        RECT 21.470 25.175 21.800 25.505 ;
        RECT 28.495 25.175 28.825 25.505 ;
        RECT 36.230 25.175 36.560 25.505 ;
        RECT 43.785 25.175 44.115 25.505 ;
        RECT 51.595 25.175 51.925 25.505 ;
        RECT 59.105 25.175 59.435 25.505 ;
        RECT 66.780 25.175 67.110 25.505 ;
        RECT 74.290 25.175 74.620 25.505 ;
        RECT 80.015 25.165 80.345 25.245 ;
        RECT 80.015 24.995 81.490 25.165 ;
        RECT 80.015 24.915 80.345 24.995 ;
        RECT 8.045 24.650 11.310 24.820 ;
        RECT 12.530 24.650 15.795 24.820 ;
        RECT 17.645 24.650 21.255 24.820 ;
        RECT 23.360 24.650 28.280 24.820 ;
        RECT 31.095 24.650 36.015 24.820 ;
        RECT 38.650 24.650 43.570 24.820 ;
        RECT 46.460 24.650 51.380 24.820 ;
        RECT 53.970 24.650 58.890 24.820 ;
        RECT 61.645 24.650 66.565 24.820 ;
        RECT 69.155 24.650 74.075 24.820 ;
        RECT 11.525 24.125 11.855 24.455 ;
        RECT 16.010 24.125 16.340 24.455 ;
        RECT 21.470 24.125 21.800 24.455 ;
        RECT 28.495 24.125 28.825 24.455 ;
        RECT 36.230 24.125 36.560 24.455 ;
        RECT 43.785 24.125 44.115 24.455 ;
        RECT 51.595 24.125 51.925 24.455 ;
        RECT 59.105 24.125 59.435 24.455 ;
        RECT 66.780 24.125 67.110 24.455 ;
        RECT 74.290 24.125 74.620 24.455 ;
        RECT 81.730 24.385 81.900 25.775 ;
        RECT 85.565 25.165 85.895 25.245 ;
        RECT 85.565 24.995 87.040 25.165 ;
        RECT 85.565 24.915 85.895 24.995 ;
        RECT 87.280 24.385 87.450 25.775 ;
        RECT 80.480 24.215 81.900 24.385 ;
        RECT 86.030 24.215 87.450 24.385 ;
        RECT 80.875 23.710 81.045 24.215 ;
        RECT 86.425 23.710 86.595 24.215 ;
        RECT 9.825 23.470 11.310 23.640 ;
        RECT 12.560 23.470 15.795 23.640 ;
        RECT 17.600 23.470 21.255 23.640 ;
        RECT 23.185 23.470 28.280 23.640 ;
        RECT 30.920 23.470 36.015 23.640 ;
        RECT 38.475 23.470 43.570 23.640 ;
        RECT 46.285 23.470 51.380 23.640 ;
        RECT 53.795 23.470 58.890 23.640 ;
        RECT 61.470 23.470 66.565 23.640 ;
        RECT 68.980 23.470 74.075 23.640 ;
        RECT 80.245 23.380 81.775 23.710 ;
        RECT 85.795 23.380 87.325 23.710 ;
        RECT 11.525 22.900 11.855 23.230 ;
        RECT 16.010 22.900 16.340 23.230 ;
        RECT 21.470 22.900 21.800 23.230 ;
        RECT 28.495 22.900 28.825 23.230 ;
        RECT 36.230 22.900 36.560 23.230 ;
        RECT 43.785 22.900 44.115 23.230 ;
        RECT 51.595 22.900 51.925 23.230 ;
        RECT 59.105 22.900 59.435 23.230 ;
        RECT 66.780 22.900 67.110 23.230 ;
        RECT 74.290 22.900 74.620 23.230 ;
        RECT 8.045 22.290 11.310 22.460 ;
        RECT 12.530 22.290 15.795 22.460 ;
        RECT 17.645 22.290 21.255 22.460 ;
        RECT 23.360 22.290 28.280 22.460 ;
        RECT 31.095 22.290 36.015 22.460 ;
        RECT 38.650 22.290 43.570 22.460 ;
        RECT 46.460 22.290 51.380 22.460 ;
        RECT 53.970 22.290 58.890 22.460 ;
        RECT 61.645 22.290 66.565 22.460 ;
        RECT 69.155 22.290 74.075 22.460 ;
        RECT 11.525 21.790 11.855 22.120 ;
        RECT 16.010 21.790 16.340 22.120 ;
        RECT 21.470 21.790 21.800 22.120 ;
        RECT 28.495 21.790 28.825 22.120 ;
        RECT 36.230 21.790 36.560 22.120 ;
        RECT 43.785 21.790 44.115 22.120 ;
        RECT 51.595 21.790 51.925 22.120 ;
        RECT 59.105 21.790 59.435 22.120 ;
        RECT 66.780 21.790 67.110 22.120 ;
        RECT 74.290 21.790 74.620 22.120 ;
        RECT 9.825 21.110 11.310 21.280 ;
        RECT 12.560 21.110 15.795 21.280 ;
        RECT 17.600 21.110 21.255 21.280 ;
        RECT 23.185 21.110 28.280 21.280 ;
        RECT 30.920 21.110 36.015 21.280 ;
        RECT 38.475 21.110 43.570 21.280 ;
        RECT 46.285 21.110 51.380 21.280 ;
        RECT 53.795 21.110 58.890 21.280 ;
        RECT 61.470 21.110 66.565 21.280 ;
        RECT 68.980 21.110 74.075 21.280 ;
        RECT 11.525 20.605 11.855 20.935 ;
        RECT 16.010 20.605 16.340 20.935 ;
        RECT 21.470 20.605 21.800 20.935 ;
        RECT 28.495 20.605 28.825 20.935 ;
        RECT 36.230 20.605 36.560 20.935 ;
        RECT 43.785 20.605 44.115 20.935 ;
        RECT 51.595 20.605 51.925 20.935 ;
        RECT 59.105 20.605 59.435 20.935 ;
        RECT 66.780 20.605 67.110 20.935 ;
        RECT 74.290 20.605 74.620 20.935 ;
        RECT 80.480 20.720 81.900 20.890 ;
        RECT 86.030 20.720 87.450 20.890 ;
        RECT 91.700 20.720 93.120 20.890 ;
        RECT 80.015 20.110 80.345 20.190 ;
        RECT 8.045 19.930 11.310 20.100 ;
        RECT 12.530 19.930 15.795 20.100 ;
        RECT 17.645 19.930 21.255 20.100 ;
        RECT 23.360 19.930 28.280 20.100 ;
        RECT 31.095 19.930 36.015 20.100 ;
        RECT 38.650 19.930 43.570 20.100 ;
        RECT 46.460 19.930 51.380 20.100 ;
        RECT 53.970 19.930 58.890 20.100 ;
        RECT 61.645 19.930 66.565 20.100 ;
        RECT 69.155 19.930 74.075 20.100 ;
        RECT 80.015 19.940 81.490 20.110 ;
        RECT 80.015 19.860 80.345 19.940 ;
        RECT 11.525 19.425 11.855 19.755 ;
        RECT 16.010 19.425 16.340 19.755 ;
        RECT 21.470 19.425 21.800 19.755 ;
        RECT 28.495 19.425 28.825 19.755 ;
        RECT 36.230 19.425 36.560 19.755 ;
        RECT 43.785 19.425 44.115 19.755 ;
        RECT 51.595 19.425 51.925 19.755 ;
        RECT 59.105 19.425 59.435 19.755 ;
        RECT 66.780 19.425 67.110 19.755 ;
        RECT 74.290 19.425 74.620 19.755 ;
        RECT 81.730 19.330 81.900 20.720 ;
        RECT 85.565 20.110 85.895 20.190 ;
        RECT 85.565 19.940 87.040 20.110 ;
        RECT 85.565 19.860 85.895 19.940 ;
        RECT 87.280 19.330 87.450 20.720 ;
        RECT 91.235 20.110 91.565 20.190 ;
        RECT 91.235 19.940 92.710 20.110 ;
        RECT 91.235 19.860 91.565 19.940 ;
        RECT 92.950 19.330 93.120 20.720 ;
        RECT 80.480 19.160 81.900 19.330 ;
        RECT 86.030 19.160 87.450 19.330 ;
        RECT 91.700 19.160 93.120 19.330 ;
        RECT 9.825 18.750 11.310 18.920 ;
        RECT 12.560 18.750 15.795 18.920 ;
        RECT 17.600 18.750 21.255 18.920 ;
        RECT 23.185 18.750 28.280 18.920 ;
        RECT 30.920 18.750 36.015 18.920 ;
        RECT 38.475 18.750 43.570 18.920 ;
        RECT 46.285 18.750 51.380 18.920 ;
        RECT 53.795 18.750 58.890 18.920 ;
        RECT 61.470 18.750 66.565 18.920 ;
        RECT 68.980 18.750 74.075 18.920 ;
        RECT 80.875 18.655 81.045 19.160 ;
        RECT 86.425 18.655 86.595 19.160 ;
        RECT 92.095 18.655 92.265 19.160 ;
        RECT 11.525 18.045 11.855 18.375 ;
        RECT 16.010 18.045 16.340 18.375 ;
        RECT 21.470 18.045 21.800 18.375 ;
        RECT 28.495 18.045 28.825 18.375 ;
        RECT 36.230 18.045 36.560 18.375 ;
        RECT 43.785 18.045 44.115 18.375 ;
        RECT 51.595 18.045 51.925 18.375 ;
        RECT 59.105 18.045 59.435 18.375 ;
        RECT 66.780 18.045 67.110 18.375 ;
        RECT 74.290 18.045 74.620 18.375 ;
        RECT 80.245 18.325 81.775 18.655 ;
        RECT 85.795 18.325 87.325 18.655 ;
        RECT 91.465 18.325 92.995 18.655 ;
        RECT 8.045 17.570 11.310 17.740 ;
        RECT 12.530 17.570 15.795 17.740 ;
        RECT 17.645 17.570 21.255 17.740 ;
        RECT 23.360 17.570 28.280 17.740 ;
        RECT 31.095 17.570 36.015 17.740 ;
        RECT 38.650 17.570 43.570 17.740 ;
        RECT 46.460 17.570 51.380 17.740 ;
        RECT 53.970 17.570 58.890 17.740 ;
        RECT 61.645 17.570 66.565 17.740 ;
        RECT 69.155 17.570 74.075 17.740 ;
        RECT 11.525 16.995 11.855 17.325 ;
        RECT 16.010 16.995 16.340 17.325 ;
        RECT 21.470 16.995 21.800 17.325 ;
        RECT 28.495 16.995 28.825 17.325 ;
        RECT 36.230 16.995 36.560 17.325 ;
        RECT 43.785 16.995 44.115 17.325 ;
        RECT 51.595 16.995 51.925 17.325 ;
        RECT 59.105 16.995 59.435 17.325 ;
        RECT 66.780 16.995 67.110 17.325 ;
        RECT 74.290 16.995 74.620 17.325 ;
        RECT 9.825 16.390 11.310 16.560 ;
        RECT 12.560 16.390 15.795 16.560 ;
        RECT 17.600 16.390 21.255 16.560 ;
        RECT 23.185 16.390 28.280 16.560 ;
        RECT 30.920 16.390 36.015 16.560 ;
        RECT 38.475 16.390 43.570 16.560 ;
        RECT 46.285 16.390 51.380 16.560 ;
        RECT 53.795 16.390 58.890 16.560 ;
        RECT 61.470 16.390 66.565 16.560 ;
        RECT 68.980 16.390 74.075 16.560 ;
        RECT 11.525 15.770 11.855 16.100 ;
        RECT 16.010 15.770 16.340 16.100 ;
        RECT 21.470 15.770 21.800 16.100 ;
        RECT 28.495 15.770 28.825 16.100 ;
        RECT 36.230 15.770 36.560 16.100 ;
        RECT 43.785 15.770 44.115 16.100 ;
        RECT 51.595 15.770 51.925 16.100 ;
        RECT 59.105 15.770 59.435 16.100 ;
        RECT 66.780 15.770 67.110 16.100 ;
        RECT 74.290 15.770 74.620 16.100 ;
        RECT 80.480 15.665 81.900 15.835 ;
        RECT 86.030 15.665 87.450 15.835 ;
        RECT 8.045 15.210 11.310 15.380 ;
        RECT 12.530 15.210 15.795 15.380 ;
        RECT 17.645 15.210 21.255 15.380 ;
        RECT 23.360 15.210 28.280 15.380 ;
        RECT 31.095 15.210 36.015 15.380 ;
        RECT 38.650 15.210 43.570 15.380 ;
        RECT 46.460 15.210 51.380 15.380 ;
        RECT 53.970 15.210 58.890 15.380 ;
        RECT 61.645 15.210 66.565 15.380 ;
        RECT 69.155 15.210 74.075 15.380 ;
        RECT 80.015 15.055 80.345 15.135 ;
        RECT 11.525 14.660 11.855 14.990 ;
        RECT 16.010 14.660 16.340 14.990 ;
        RECT 21.470 14.660 21.800 14.990 ;
        RECT 28.495 14.660 28.825 14.990 ;
        RECT 36.230 14.660 36.560 14.990 ;
        RECT 43.785 14.660 44.115 14.990 ;
        RECT 51.595 14.660 51.925 14.990 ;
        RECT 59.105 14.660 59.435 14.990 ;
        RECT 66.780 14.660 67.110 14.990 ;
        RECT 74.290 14.660 74.620 14.990 ;
        RECT 80.015 14.885 81.490 15.055 ;
        RECT 80.015 14.805 80.345 14.885 ;
        RECT 81.730 14.275 81.900 15.665 ;
        RECT 85.565 15.055 85.895 15.135 ;
        RECT 85.565 14.885 87.040 15.055 ;
        RECT 85.565 14.805 85.895 14.885 ;
        RECT 87.280 14.275 87.450 15.665 ;
        RECT 91.235 15.055 91.565 15.135 ;
        RECT 91.235 14.885 92.710 15.055 ;
        RECT 91.235 14.805 91.565 14.885 ;
        RECT 9.825 14.030 11.310 14.200 ;
        RECT 12.560 14.030 15.795 14.200 ;
        RECT 17.600 14.030 21.255 14.200 ;
        RECT 23.185 14.030 28.280 14.200 ;
        RECT 30.920 14.030 36.015 14.200 ;
        RECT 38.475 14.030 43.570 14.200 ;
        RECT 46.285 14.030 51.380 14.200 ;
        RECT 53.795 14.030 58.890 14.200 ;
        RECT 61.470 14.030 66.565 14.200 ;
        RECT 68.980 14.030 74.075 14.200 ;
        RECT 80.480 14.105 81.900 14.275 ;
        RECT 86.030 14.105 87.450 14.275 ;
        RECT 11.525 13.475 11.855 13.805 ;
        RECT 16.010 13.475 16.340 13.805 ;
        RECT 21.470 13.475 21.800 13.805 ;
        RECT 28.495 13.475 28.825 13.805 ;
        RECT 36.230 13.475 36.560 13.805 ;
        RECT 43.785 13.475 44.115 13.805 ;
        RECT 51.595 13.475 51.925 13.805 ;
        RECT 59.105 13.475 59.435 13.805 ;
        RECT 66.780 13.475 67.110 13.805 ;
        RECT 74.290 13.475 74.620 13.805 ;
        RECT 80.875 13.600 81.045 14.105 ;
        RECT 86.425 13.600 86.595 14.105 ;
        RECT 80.245 13.270 81.775 13.600 ;
        RECT 85.795 13.270 87.325 13.600 ;
        RECT 8.045 12.850 11.310 13.020 ;
        RECT 12.530 12.850 15.795 13.020 ;
        RECT 17.645 12.850 21.255 13.020 ;
        RECT 23.360 12.850 28.280 13.020 ;
        RECT 31.095 12.850 36.015 13.020 ;
        RECT 38.650 12.850 43.570 13.020 ;
        RECT 46.460 12.850 51.380 13.020 ;
        RECT 53.970 12.850 58.890 13.020 ;
        RECT 61.645 12.850 66.565 13.020 ;
        RECT 69.155 12.850 74.075 13.020 ;
        RECT 11.525 12.295 11.855 12.625 ;
        RECT 16.010 12.295 16.340 12.625 ;
        RECT 21.470 12.295 21.800 12.625 ;
        RECT 28.495 12.295 28.825 12.625 ;
        RECT 36.230 12.295 36.560 12.625 ;
        RECT 43.785 12.295 44.115 12.625 ;
        RECT 51.595 12.295 51.925 12.625 ;
        RECT 59.105 12.295 59.435 12.625 ;
        RECT 66.780 12.295 67.110 12.625 ;
        RECT 74.290 12.295 74.620 12.625 ;
        RECT 9.825 11.670 11.310 11.840 ;
        RECT 12.560 11.670 15.795 11.840 ;
        RECT 17.600 11.670 21.255 11.840 ;
        RECT 23.185 11.670 28.280 11.840 ;
        RECT 30.920 11.670 36.015 11.840 ;
        RECT 38.475 11.670 43.570 11.840 ;
        RECT 46.285 11.670 51.380 11.840 ;
        RECT 53.795 11.670 58.890 11.840 ;
        RECT 61.470 11.670 66.565 11.840 ;
        RECT 68.980 11.670 74.075 11.840 ;
      LAYER met1 ;
        RECT 8.080 48.800 9.360 48.820 ;
        RECT 8.035 48.570 9.405 48.800 ;
        RECT 12.565 48.765 13.845 48.785 ;
        RECT 18.025 48.765 19.305 48.785 ;
        RECT 25.050 48.765 26.330 48.785 ;
        RECT 32.785 48.765 34.065 48.785 ;
        RECT 40.340 48.765 41.620 48.785 ;
        RECT 48.150 48.765 49.430 48.785 ;
        RECT 55.660 48.765 56.940 48.785 ;
        RECT 63.335 48.765 64.615 48.785 ;
        RECT 70.845 48.765 72.125 48.785 ;
        RECT 8.080 48.560 9.360 48.570 ;
        RECT 12.520 48.535 13.890 48.765 ;
        RECT 17.980 48.535 19.350 48.765 ;
        RECT 25.005 48.535 26.375 48.765 ;
        RECT 32.740 48.535 34.110 48.765 ;
        RECT 40.295 48.535 41.665 48.765 ;
        RECT 48.105 48.535 49.475 48.765 ;
        RECT 55.615 48.535 56.985 48.765 ;
        RECT 63.290 48.535 64.660 48.765 ;
        RECT 70.800 48.535 72.170 48.765 ;
        RECT 12.565 48.525 13.845 48.535 ;
        RECT 18.025 48.525 19.305 48.535 ;
        RECT 25.050 48.525 26.330 48.535 ;
        RECT 32.785 48.525 34.065 48.535 ;
        RECT 40.340 48.525 41.620 48.535 ;
        RECT 48.150 48.525 49.430 48.535 ;
        RECT 55.660 48.525 56.940 48.535 ;
        RECT 63.335 48.525 64.615 48.535 ;
        RECT 70.845 48.525 72.125 48.535 ;
        RECT 10.105 46.920 75.990 47.580 ;
        RECT 8.080 46.085 9.360 46.105 ;
        RECT 8.035 45.855 9.405 46.085 ;
        RECT 8.080 45.845 9.360 45.855 ;
        RECT 10.385 44.680 11.035 44.910 ;
        RECT 10.385 44.650 11.025 44.680 ;
        RECT 8.080 43.725 9.360 43.745 ;
        RECT 8.035 43.495 9.405 43.725 ;
        RECT 8.080 43.485 9.360 43.495 ;
        RECT 10.385 42.550 11.025 42.560 ;
        RECT 10.385 42.320 11.035 42.550 ;
        RECT 10.385 42.300 11.025 42.320 ;
        RECT 8.080 41.370 9.360 41.390 ;
        RECT 8.035 41.140 9.405 41.370 ;
        RECT 8.080 41.130 9.360 41.140 ;
        RECT 11.545 40.810 11.835 46.605 ;
        RECT 12.565 46.085 13.845 46.105 ;
        RECT 12.520 45.855 13.890 46.085 ;
        RECT 12.565 45.845 13.845 45.855 ;
        RECT 14.870 44.680 15.520 44.910 ;
        RECT 14.870 44.650 15.510 44.680 ;
        RECT 12.565 43.725 13.845 43.745 ;
        RECT 12.520 43.495 13.890 43.725 ;
        RECT 12.565 43.485 13.845 43.495 ;
        RECT 14.870 42.550 15.510 42.560 ;
        RECT 14.870 42.320 15.520 42.550 ;
        RECT 14.870 42.300 15.510 42.320 ;
        RECT 12.565 41.370 13.845 41.390 ;
        RECT 12.520 41.140 13.890 41.370 ;
        RECT 12.565 41.130 13.845 41.140 ;
        RECT 16.030 40.810 16.320 46.605 ;
        RECT 18.025 46.085 19.305 46.105 ;
        RECT 17.980 45.855 19.350 46.085 ;
        RECT 18.025 45.845 19.305 45.855 ;
        RECT 20.330 44.680 20.980 44.910 ;
        RECT 20.330 44.650 20.970 44.680 ;
        RECT 18.025 43.725 19.305 43.745 ;
        RECT 17.980 43.495 19.350 43.725 ;
        RECT 18.025 43.485 19.305 43.495 ;
        RECT 20.330 42.550 20.970 42.560 ;
        RECT 20.330 42.320 20.980 42.550 ;
        RECT 20.330 42.300 20.970 42.320 ;
        RECT 18.025 41.370 19.305 41.390 ;
        RECT 17.980 41.140 19.350 41.370 ;
        RECT 18.025 41.130 19.305 41.140 ;
        RECT 21.490 40.810 21.780 46.605 ;
        RECT 25.050 46.085 26.330 46.105 ;
        RECT 25.005 45.855 26.375 46.085 ;
        RECT 25.050 45.845 26.330 45.855 ;
        RECT 27.355 44.680 28.005 44.910 ;
        RECT 27.355 44.650 27.995 44.680 ;
        RECT 25.050 43.725 26.330 43.745 ;
        RECT 25.005 43.495 26.375 43.725 ;
        RECT 25.050 43.485 26.330 43.495 ;
        RECT 27.355 42.550 27.995 42.560 ;
        RECT 27.355 42.320 28.005 42.550 ;
        RECT 27.355 42.300 27.995 42.320 ;
        RECT 25.050 41.370 26.330 41.390 ;
        RECT 25.005 41.140 26.375 41.370 ;
        RECT 25.050 41.130 26.330 41.140 ;
        RECT 28.515 40.810 28.805 46.605 ;
        RECT 32.785 46.085 34.065 46.105 ;
        RECT 32.740 45.855 34.110 46.085 ;
        RECT 32.785 45.845 34.065 45.855 ;
        RECT 35.090 44.680 35.740 44.910 ;
        RECT 35.090 44.650 35.730 44.680 ;
        RECT 32.785 43.725 34.065 43.745 ;
        RECT 32.740 43.495 34.110 43.725 ;
        RECT 32.785 43.485 34.065 43.495 ;
        RECT 35.090 42.550 35.730 42.560 ;
        RECT 35.090 42.320 35.740 42.550 ;
        RECT 35.090 42.300 35.730 42.320 ;
        RECT 32.785 41.370 34.065 41.390 ;
        RECT 32.740 41.140 34.110 41.370 ;
        RECT 32.785 41.130 34.065 41.140 ;
        RECT 36.250 40.810 36.540 46.605 ;
        RECT 40.340 46.085 41.620 46.105 ;
        RECT 40.295 45.855 41.665 46.085 ;
        RECT 40.340 45.845 41.620 45.855 ;
        RECT 42.645 44.680 43.295 44.910 ;
        RECT 42.645 44.650 43.285 44.680 ;
        RECT 40.340 43.725 41.620 43.745 ;
        RECT 40.295 43.495 41.665 43.725 ;
        RECT 40.340 43.485 41.620 43.495 ;
        RECT 42.645 42.550 43.285 42.560 ;
        RECT 42.645 42.320 43.295 42.550 ;
        RECT 42.645 42.300 43.285 42.320 ;
        RECT 40.340 41.370 41.620 41.390 ;
        RECT 40.295 41.140 41.665 41.370 ;
        RECT 40.340 41.130 41.620 41.140 ;
        RECT 43.805 40.810 44.095 46.605 ;
        RECT 48.150 46.085 49.430 46.105 ;
        RECT 48.105 45.855 49.475 46.085 ;
        RECT 48.150 45.845 49.430 45.855 ;
        RECT 50.455 44.680 51.105 44.910 ;
        RECT 50.455 44.650 51.095 44.680 ;
        RECT 48.150 43.725 49.430 43.745 ;
        RECT 48.105 43.495 49.475 43.725 ;
        RECT 48.150 43.485 49.430 43.495 ;
        RECT 50.455 42.550 51.095 42.560 ;
        RECT 50.455 42.320 51.105 42.550 ;
        RECT 50.455 42.300 51.095 42.320 ;
        RECT 48.150 41.370 49.430 41.390 ;
        RECT 48.105 41.140 49.475 41.370 ;
        RECT 48.150 41.130 49.430 41.140 ;
        RECT 51.615 40.810 51.905 46.605 ;
        RECT 55.660 46.085 56.940 46.105 ;
        RECT 55.615 45.855 56.985 46.085 ;
        RECT 55.660 45.845 56.940 45.855 ;
        RECT 57.965 44.680 58.615 44.910 ;
        RECT 57.965 44.650 58.605 44.680 ;
        RECT 55.660 43.725 56.940 43.745 ;
        RECT 55.615 43.495 56.985 43.725 ;
        RECT 55.660 43.485 56.940 43.495 ;
        RECT 57.965 42.550 58.605 42.560 ;
        RECT 57.965 42.320 58.615 42.550 ;
        RECT 57.965 42.300 58.605 42.320 ;
        RECT 55.660 41.370 56.940 41.390 ;
        RECT 55.615 41.140 56.985 41.370 ;
        RECT 55.660 41.130 56.940 41.140 ;
        RECT 59.125 40.810 59.415 46.605 ;
        RECT 63.335 46.085 64.615 46.105 ;
        RECT 63.290 45.855 64.660 46.085 ;
        RECT 63.335 45.845 64.615 45.855 ;
        RECT 65.640 44.680 66.290 44.910 ;
        RECT 65.640 44.650 66.280 44.680 ;
        RECT 63.335 43.725 64.615 43.745 ;
        RECT 63.290 43.495 64.660 43.725 ;
        RECT 63.335 43.485 64.615 43.495 ;
        RECT 65.640 42.550 66.280 42.560 ;
        RECT 65.640 42.320 66.290 42.550 ;
        RECT 65.640 42.300 66.280 42.320 ;
        RECT 63.335 41.370 64.615 41.390 ;
        RECT 63.290 41.140 64.660 41.370 ;
        RECT 63.335 41.130 64.615 41.140 ;
        RECT 66.800 40.810 67.090 46.605 ;
        RECT 70.845 46.085 72.125 46.105 ;
        RECT 70.800 45.855 72.170 46.085 ;
        RECT 70.845 45.845 72.125 45.855 ;
        RECT 73.150 44.680 73.800 44.910 ;
        RECT 73.150 44.650 73.790 44.680 ;
        RECT 70.845 43.725 72.125 43.745 ;
        RECT 70.800 43.495 72.170 43.725 ;
        RECT 70.845 43.485 72.125 43.495 ;
        RECT 73.150 42.550 73.790 42.560 ;
        RECT 73.150 42.320 73.800 42.550 ;
        RECT 73.150 42.300 73.790 42.320 ;
        RECT 70.845 41.370 72.125 41.390 ;
        RECT 70.800 41.140 72.170 41.370 ;
        RECT 70.845 41.130 72.125 41.140 ;
        RECT 74.310 40.810 74.600 46.605 ;
        RECT 75.340 45.535 75.990 46.920 ;
        RECT 75.340 45.165 83.255 45.535 ;
        RECT 75.350 45.155 83.255 45.165 ;
        RECT 83.550 45.155 87.110 45.535 ;
        RECT 80.845 43.620 81.135 43.910 ;
        RECT 11.545 40.430 74.605 40.810 ;
        RECT 80.920 40.430 81.060 43.620 ;
        RECT 10.385 40.190 11.025 40.200 ;
        RECT 10.385 39.960 11.035 40.190 ;
        RECT 10.385 39.940 11.025 39.960 ;
        RECT 8.080 39.010 9.360 39.030 ;
        RECT 8.035 38.780 9.405 39.010 ;
        RECT 8.080 38.770 9.360 38.780 ;
        RECT 10.385 37.830 11.025 37.845 ;
        RECT 10.385 37.600 11.035 37.830 ;
        RECT 10.385 37.585 11.025 37.600 ;
        RECT 8.080 36.650 9.360 36.670 ;
        RECT 8.035 36.420 9.405 36.650 ;
        RECT 8.080 36.410 9.360 36.420 ;
        RECT 10.385 35.470 11.025 35.485 ;
        RECT 10.385 35.240 11.035 35.470 ;
        RECT 10.385 35.225 11.025 35.240 ;
        RECT 8.080 34.290 9.360 34.310 ;
        RECT 8.035 34.060 9.405 34.290 ;
        RECT 8.080 34.050 9.360 34.060 ;
        RECT 10.385 33.110 11.025 33.120 ;
        RECT 10.385 32.880 11.035 33.110 ;
        RECT 10.385 32.860 11.025 32.880 ;
        RECT 8.080 31.930 9.360 31.950 ;
        RECT 8.035 31.700 9.405 31.930 ;
        RECT 8.080 31.690 9.360 31.700 ;
        RECT 10.385 30.750 11.025 30.765 ;
        RECT 10.385 30.520 11.035 30.750 ;
        RECT 10.385 30.505 11.025 30.520 ;
        RECT 8.080 29.570 9.360 29.590 ;
        RECT 8.035 29.340 9.405 29.570 ;
        RECT 8.080 29.330 9.360 29.340 ;
        RECT 11.545 29.105 11.835 40.430 ;
        RECT 14.870 40.190 15.510 40.200 ;
        RECT 14.870 39.960 15.520 40.190 ;
        RECT 14.870 39.940 15.510 39.960 ;
        RECT 12.565 39.010 13.845 39.030 ;
        RECT 12.520 38.780 13.890 39.010 ;
        RECT 12.565 38.770 13.845 38.780 ;
        RECT 14.870 37.830 15.510 37.845 ;
        RECT 14.870 37.600 15.520 37.830 ;
        RECT 14.870 37.585 15.510 37.600 ;
        RECT 12.565 36.650 13.845 36.670 ;
        RECT 12.520 36.420 13.890 36.650 ;
        RECT 12.565 36.410 13.845 36.420 ;
        RECT 14.870 35.470 15.510 35.485 ;
        RECT 14.870 35.240 15.520 35.470 ;
        RECT 14.870 35.225 15.510 35.240 ;
        RECT 12.565 34.290 13.845 34.310 ;
        RECT 12.520 34.060 13.890 34.290 ;
        RECT 12.565 34.050 13.845 34.060 ;
        RECT 14.870 33.110 15.510 33.120 ;
        RECT 14.870 32.880 15.520 33.110 ;
        RECT 14.870 32.860 15.510 32.880 ;
        RECT 12.565 31.930 13.845 31.950 ;
        RECT 12.520 31.700 13.890 31.930 ;
        RECT 12.565 31.690 13.845 31.700 ;
        RECT 14.870 30.750 15.510 30.765 ;
        RECT 14.870 30.520 15.520 30.750 ;
        RECT 14.870 30.505 15.510 30.520 ;
        RECT 12.565 29.570 13.845 29.590 ;
        RECT 12.520 29.340 13.890 29.570 ;
        RECT 12.565 29.330 13.845 29.340 ;
        RECT 16.030 29.105 16.320 40.430 ;
        RECT 20.330 40.190 20.970 40.200 ;
        RECT 20.330 39.960 20.980 40.190 ;
        RECT 20.330 39.940 20.970 39.960 ;
        RECT 18.025 39.010 19.305 39.030 ;
        RECT 17.980 38.780 19.350 39.010 ;
        RECT 18.025 38.770 19.305 38.780 ;
        RECT 20.330 37.830 20.970 37.845 ;
        RECT 20.330 37.600 20.980 37.830 ;
        RECT 20.330 37.585 20.970 37.600 ;
        RECT 18.025 36.650 19.305 36.670 ;
        RECT 17.980 36.420 19.350 36.650 ;
        RECT 18.025 36.410 19.305 36.420 ;
        RECT 20.330 35.470 20.970 35.485 ;
        RECT 20.330 35.240 20.980 35.470 ;
        RECT 20.330 35.225 20.970 35.240 ;
        RECT 18.025 34.290 19.305 34.310 ;
        RECT 17.980 34.060 19.350 34.290 ;
        RECT 18.025 34.050 19.305 34.060 ;
        RECT 20.330 33.110 20.970 33.120 ;
        RECT 20.330 32.880 20.980 33.110 ;
        RECT 20.330 32.860 20.970 32.880 ;
        RECT 18.025 31.930 19.305 31.950 ;
        RECT 17.980 31.700 19.350 31.930 ;
        RECT 18.025 31.690 19.305 31.700 ;
        RECT 20.330 30.750 20.970 30.765 ;
        RECT 20.330 30.520 20.980 30.750 ;
        RECT 20.330 30.505 20.970 30.520 ;
        RECT 18.025 29.570 19.305 29.590 ;
        RECT 17.980 29.340 19.350 29.570 ;
        RECT 18.025 29.330 19.305 29.340 ;
        RECT 21.490 29.105 21.780 40.430 ;
        RECT 27.355 40.190 27.995 40.200 ;
        RECT 27.355 39.960 28.005 40.190 ;
        RECT 27.355 39.940 27.995 39.960 ;
        RECT 25.050 39.010 26.330 39.030 ;
        RECT 25.005 38.780 26.375 39.010 ;
        RECT 25.050 38.770 26.330 38.780 ;
        RECT 27.355 37.830 27.995 37.845 ;
        RECT 27.355 37.600 28.005 37.830 ;
        RECT 27.355 37.585 27.995 37.600 ;
        RECT 25.050 36.650 26.330 36.670 ;
        RECT 25.005 36.420 26.375 36.650 ;
        RECT 25.050 36.410 26.330 36.420 ;
        RECT 27.355 35.470 27.995 35.485 ;
        RECT 27.355 35.240 28.005 35.470 ;
        RECT 27.355 35.225 27.995 35.240 ;
        RECT 25.050 34.290 26.330 34.310 ;
        RECT 25.005 34.060 26.375 34.290 ;
        RECT 25.050 34.050 26.330 34.060 ;
        RECT 27.355 33.110 27.995 33.120 ;
        RECT 27.355 32.880 28.005 33.110 ;
        RECT 27.355 32.860 27.995 32.880 ;
        RECT 25.050 31.930 26.330 31.950 ;
        RECT 25.005 31.700 26.375 31.930 ;
        RECT 25.050 31.690 26.330 31.700 ;
        RECT 27.355 30.750 27.995 30.765 ;
        RECT 27.355 30.520 28.005 30.750 ;
        RECT 27.355 30.505 27.995 30.520 ;
        RECT 25.050 29.570 26.330 29.590 ;
        RECT 25.005 29.340 26.375 29.570 ;
        RECT 25.050 29.330 26.330 29.340 ;
        RECT 28.515 29.105 28.805 40.430 ;
        RECT 35.090 40.190 35.730 40.200 ;
        RECT 35.090 39.960 35.740 40.190 ;
        RECT 35.090 39.940 35.730 39.960 ;
        RECT 32.785 39.010 34.065 39.030 ;
        RECT 32.740 38.780 34.110 39.010 ;
        RECT 32.785 38.770 34.065 38.780 ;
        RECT 35.090 37.830 35.730 37.845 ;
        RECT 35.090 37.600 35.740 37.830 ;
        RECT 35.090 37.585 35.730 37.600 ;
        RECT 32.785 36.650 34.065 36.670 ;
        RECT 32.740 36.420 34.110 36.650 ;
        RECT 32.785 36.410 34.065 36.420 ;
        RECT 35.090 35.470 35.730 35.485 ;
        RECT 35.090 35.240 35.740 35.470 ;
        RECT 35.090 35.225 35.730 35.240 ;
        RECT 32.785 34.290 34.065 34.310 ;
        RECT 32.740 34.060 34.110 34.290 ;
        RECT 32.785 34.050 34.065 34.060 ;
        RECT 35.090 33.110 35.730 33.120 ;
        RECT 35.090 32.880 35.740 33.110 ;
        RECT 35.090 32.860 35.730 32.880 ;
        RECT 32.785 31.930 34.065 31.950 ;
        RECT 32.740 31.700 34.110 31.930 ;
        RECT 32.785 31.690 34.065 31.700 ;
        RECT 35.090 30.750 35.730 30.765 ;
        RECT 35.090 30.520 35.740 30.750 ;
        RECT 35.090 30.505 35.730 30.520 ;
        RECT 32.785 29.570 34.065 29.590 ;
        RECT 32.740 29.340 34.110 29.570 ;
        RECT 32.785 29.330 34.065 29.340 ;
        RECT 36.250 29.105 36.540 40.430 ;
        RECT 42.645 40.190 43.285 40.200 ;
        RECT 42.645 39.960 43.295 40.190 ;
        RECT 42.645 39.940 43.285 39.960 ;
        RECT 40.340 39.010 41.620 39.030 ;
        RECT 40.295 38.780 41.665 39.010 ;
        RECT 40.340 38.770 41.620 38.780 ;
        RECT 42.645 37.830 43.285 37.845 ;
        RECT 42.645 37.600 43.295 37.830 ;
        RECT 42.645 37.585 43.285 37.600 ;
        RECT 40.340 36.650 41.620 36.670 ;
        RECT 40.295 36.420 41.665 36.650 ;
        RECT 40.340 36.410 41.620 36.420 ;
        RECT 42.645 35.470 43.285 35.485 ;
        RECT 42.645 35.240 43.295 35.470 ;
        RECT 42.645 35.225 43.285 35.240 ;
        RECT 40.340 34.290 41.620 34.310 ;
        RECT 40.295 34.060 41.665 34.290 ;
        RECT 40.340 34.050 41.620 34.060 ;
        RECT 42.645 33.110 43.285 33.120 ;
        RECT 42.645 32.880 43.295 33.110 ;
        RECT 42.645 32.860 43.285 32.880 ;
        RECT 40.340 31.930 41.620 31.950 ;
        RECT 40.295 31.700 41.665 31.930 ;
        RECT 40.340 31.690 41.620 31.700 ;
        RECT 42.645 30.750 43.285 30.765 ;
        RECT 42.645 30.520 43.295 30.750 ;
        RECT 42.645 30.505 43.285 30.520 ;
        RECT 40.340 29.570 41.620 29.590 ;
        RECT 40.295 29.340 41.665 29.570 ;
        RECT 40.340 29.330 41.620 29.340 ;
        RECT 43.805 29.105 44.095 40.430 ;
        RECT 50.455 40.190 51.095 40.200 ;
        RECT 50.455 39.960 51.105 40.190 ;
        RECT 50.455 39.940 51.095 39.960 ;
        RECT 48.150 39.010 49.430 39.030 ;
        RECT 48.105 38.780 49.475 39.010 ;
        RECT 48.150 38.770 49.430 38.780 ;
        RECT 50.455 37.830 51.095 37.845 ;
        RECT 50.455 37.600 51.105 37.830 ;
        RECT 50.455 37.585 51.095 37.600 ;
        RECT 48.150 36.650 49.430 36.670 ;
        RECT 48.105 36.420 49.475 36.650 ;
        RECT 48.150 36.410 49.430 36.420 ;
        RECT 50.455 35.470 51.095 35.485 ;
        RECT 50.455 35.240 51.105 35.470 ;
        RECT 50.455 35.225 51.095 35.240 ;
        RECT 48.150 34.290 49.430 34.310 ;
        RECT 48.105 34.060 49.475 34.290 ;
        RECT 48.150 34.050 49.430 34.060 ;
        RECT 50.455 33.110 51.095 33.120 ;
        RECT 50.455 32.880 51.105 33.110 ;
        RECT 50.455 32.860 51.095 32.880 ;
        RECT 48.150 31.930 49.430 31.950 ;
        RECT 48.105 31.700 49.475 31.930 ;
        RECT 48.150 31.690 49.430 31.700 ;
        RECT 50.455 30.750 51.095 30.765 ;
        RECT 50.455 30.520 51.105 30.750 ;
        RECT 50.455 30.505 51.095 30.520 ;
        RECT 48.150 29.570 49.430 29.590 ;
        RECT 48.105 29.340 49.475 29.570 ;
        RECT 48.150 29.330 49.430 29.340 ;
        RECT 51.615 29.105 51.905 40.430 ;
        RECT 57.965 40.190 58.605 40.200 ;
        RECT 57.965 39.960 58.615 40.190 ;
        RECT 57.965 39.940 58.605 39.960 ;
        RECT 55.660 39.010 56.940 39.030 ;
        RECT 55.615 38.780 56.985 39.010 ;
        RECT 55.660 38.770 56.940 38.780 ;
        RECT 57.965 37.830 58.605 37.845 ;
        RECT 57.965 37.600 58.615 37.830 ;
        RECT 57.965 37.585 58.605 37.600 ;
        RECT 55.660 36.650 56.940 36.670 ;
        RECT 55.615 36.420 56.985 36.650 ;
        RECT 55.660 36.410 56.940 36.420 ;
        RECT 57.965 35.470 58.605 35.485 ;
        RECT 57.965 35.240 58.615 35.470 ;
        RECT 57.965 35.225 58.605 35.240 ;
        RECT 55.660 34.290 56.940 34.310 ;
        RECT 55.615 34.060 56.985 34.290 ;
        RECT 55.660 34.050 56.940 34.060 ;
        RECT 57.965 33.110 58.605 33.120 ;
        RECT 57.965 32.880 58.615 33.110 ;
        RECT 57.965 32.860 58.605 32.880 ;
        RECT 55.660 31.930 56.940 31.950 ;
        RECT 55.615 31.700 56.985 31.930 ;
        RECT 55.660 31.690 56.940 31.700 ;
        RECT 57.965 30.750 58.605 30.765 ;
        RECT 57.965 30.520 58.615 30.750 ;
        RECT 57.965 30.505 58.605 30.520 ;
        RECT 55.660 29.570 56.940 29.590 ;
        RECT 55.615 29.340 56.985 29.570 ;
        RECT 55.660 29.330 56.940 29.340 ;
        RECT 59.125 29.105 59.415 40.430 ;
        RECT 65.640 40.190 66.280 40.200 ;
        RECT 65.640 39.960 66.290 40.190 ;
        RECT 65.640 39.940 66.280 39.960 ;
        RECT 63.335 39.010 64.615 39.030 ;
        RECT 63.290 38.780 64.660 39.010 ;
        RECT 63.335 38.770 64.615 38.780 ;
        RECT 65.640 37.830 66.280 37.845 ;
        RECT 65.640 37.600 66.290 37.830 ;
        RECT 65.640 37.585 66.280 37.600 ;
        RECT 63.335 36.650 64.615 36.670 ;
        RECT 63.290 36.420 64.660 36.650 ;
        RECT 63.335 36.410 64.615 36.420 ;
        RECT 65.640 35.470 66.280 35.485 ;
        RECT 65.640 35.240 66.290 35.470 ;
        RECT 65.640 35.225 66.280 35.240 ;
        RECT 63.335 34.290 64.615 34.310 ;
        RECT 63.290 34.060 64.660 34.290 ;
        RECT 63.335 34.050 64.615 34.060 ;
        RECT 65.640 33.110 66.280 33.120 ;
        RECT 65.640 32.880 66.290 33.110 ;
        RECT 65.640 32.860 66.280 32.880 ;
        RECT 63.335 31.930 64.615 31.950 ;
        RECT 63.290 31.700 64.660 31.930 ;
        RECT 63.335 31.690 64.615 31.700 ;
        RECT 65.640 30.750 66.280 30.765 ;
        RECT 65.640 30.520 66.290 30.750 ;
        RECT 65.640 30.505 66.280 30.520 ;
        RECT 63.335 29.570 64.615 29.590 ;
        RECT 63.290 29.340 64.660 29.570 ;
        RECT 63.335 29.330 64.615 29.340 ;
        RECT 66.800 29.105 67.090 40.430 ;
        RECT 73.150 40.190 73.790 40.200 ;
        RECT 73.150 39.960 73.800 40.190 ;
        RECT 74.310 40.050 83.040 40.430 ;
        RECT 73.150 39.940 73.790 39.960 ;
        RECT 70.845 39.010 72.125 39.030 ;
        RECT 70.800 38.780 72.170 39.010 ;
        RECT 70.845 38.770 72.125 38.780 ;
        RECT 73.150 37.830 73.790 37.845 ;
        RECT 73.150 37.600 73.800 37.830 ;
        RECT 73.150 37.585 73.790 37.600 ;
        RECT 70.845 36.650 72.125 36.670 ;
        RECT 70.800 36.420 72.170 36.650 ;
        RECT 70.845 36.410 72.125 36.420 ;
        RECT 73.150 35.470 73.790 35.485 ;
        RECT 73.150 35.240 73.800 35.470 ;
        RECT 73.150 35.225 73.790 35.240 ;
        RECT 70.845 34.290 72.125 34.310 ;
        RECT 70.800 34.060 72.170 34.290 ;
        RECT 70.845 34.050 72.125 34.060 ;
        RECT 73.150 33.110 73.790 33.120 ;
        RECT 73.150 32.880 73.800 33.110 ;
        RECT 73.150 32.860 73.790 32.880 ;
        RECT 70.845 31.930 72.125 31.950 ;
        RECT 70.800 31.700 72.170 31.930 ;
        RECT 70.845 31.690 72.125 31.700 ;
        RECT 73.150 30.750 73.790 30.765 ;
        RECT 73.150 30.520 73.800 30.750 ;
        RECT 73.150 30.505 73.790 30.520 ;
        RECT 70.845 29.570 72.125 29.590 ;
        RECT 70.800 29.340 72.170 29.570 ;
        RECT 70.845 29.330 72.125 29.340 ;
        RECT 74.310 29.105 74.600 40.050 ;
        RECT 80.845 38.565 81.135 38.855 ;
        RECT 80.920 35.335 81.060 38.565 ;
        RECT 80.845 35.045 81.135 35.335 ;
        RECT 80.845 33.510 81.135 33.800 ;
        RECT 80.920 30.280 81.060 33.510 ;
        RECT 80.845 29.990 81.135 30.280 ;
        RECT 11.530 28.725 74.605 29.105 ;
        RECT 10.385 28.390 11.025 28.405 ;
        RECT 10.385 28.160 11.035 28.390 ;
        RECT 10.385 28.145 11.025 28.160 ;
        RECT 8.080 27.210 9.360 27.230 ;
        RECT 8.035 26.980 9.405 27.210 ;
        RECT 8.080 26.970 9.360 26.980 ;
        RECT 10.385 26.030 11.025 26.040 ;
        RECT 10.385 25.800 11.035 26.030 ;
        RECT 10.385 25.780 11.025 25.800 ;
        RECT 8.080 24.850 9.360 24.870 ;
        RECT 8.035 24.620 9.405 24.850 ;
        RECT 8.080 24.610 9.360 24.620 ;
        RECT 10.385 23.670 11.025 23.680 ;
        RECT 10.385 23.440 11.035 23.670 ;
        RECT 10.385 23.420 11.025 23.440 ;
        RECT 8.080 22.490 9.360 22.510 ;
        RECT 8.035 22.260 9.405 22.490 ;
        RECT 8.080 22.250 9.360 22.260 ;
        RECT 10.385 21.310 11.025 21.325 ;
        RECT 10.385 21.080 11.035 21.310 ;
        RECT 10.385 21.065 11.025 21.080 ;
        RECT 8.080 20.130 9.360 20.150 ;
        RECT 8.035 19.900 9.405 20.130 ;
        RECT 8.080 19.890 9.360 19.900 ;
        RECT 10.385 18.950 11.025 18.965 ;
        RECT 10.385 18.720 11.035 18.950 ;
        RECT 10.385 18.705 11.025 18.720 ;
        RECT 8.080 17.770 9.360 17.790 ;
        RECT 8.035 17.540 9.405 17.770 ;
        RECT 8.080 17.530 9.360 17.540 ;
        RECT 11.545 17.295 11.835 28.725 ;
        RECT 14.870 28.390 15.510 28.405 ;
        RECT 14.870 28.160 15.520 28.390 ;
        RECT 14.870 28.145 15.510 28.160 ;
        RECT 12.565 27.210 13.845 27.230 ;
        RECT 12.520 26.980 13.890 27.210 ;
        RECT 12.565 26.970 13.845 26.980 ;
        RECT 14.870 26.030 15.510 26.040 ;
        RECT 14.870 25.800 15.520 26.030 ;
        RECT 14.870 25.780 15.510 25.800 ;
        RECT 12.565 24.850 13.845 24.870 ;
        RECT 12.520 24.620 13.890 24.850 ;
        RECT 12.565 24.610 13.845 24.620 ;
        RECT 14.870 23.670 15.510 23.680 ;
        RECT 14.870 23.440 15.520 23.670 ;
        RECT 14.870 23.420 15.510 23.440 ;
        RECT 12.565 22.490 13.845 22.510 ;
        RECT 12.520 22.260 13.890 22.490 ;
        RECT 12.565 22.250 13.845 22.260 ;
        RECT 14.870 21.310 15.510 21.325 ;
        RECT 14.870 21.080 15.520 21.310 ;
        RECT 14.870 21.065 15.510 21.080 ;
        RECT 12.565 20.130 13.845 20.150 ;
        RECT 12.520 19.900 13.890 20.130 ;
        RECT 12.565 19.890 13.845 19.900 ;
        RECT 14.870 18.950 15.510 18.965 ;
        RECT 14.870 18.720 15.520 18.950 ;
        RECT 14.870 18.705 15.510 18.720 ;
        RECT 12.565 17.770 13.845 17.790 ;
        RECT 12.520 17.540 13.890 17.770 ;
        RECT 12.565 17.530 13.845 17.540 ;
        RECT 16.030 17.295 16.320 28.725 ;
        RECT 20.330 28.390 20.970 28.405 ;
        RECT 20.330 28.160 20.980 28.390 ;
        RECT 20.330 28.145 20.970 28.160 ;
        RECT 18.025 27.210 19.305 27.230 ;
        RECT 17.980 26.980 19.350 27.210 ;
        RECT 18.025 26.970 19.305 26.980 ;
        RECT 20.330 26.030 20.970 26.040 ;
        RECT 20.330 25.800 20.980 26.030 ;
        RECT 20.330 25.780 20.970 25.800 ;
        RECT 18.025 24.850 19.305 24.870 ;
        RECT 17.980 24.620 19.350 24.850 ;
        RECT 18.025 24.610 19.305 24.620 ;
        RECT 20.330 23.670 20.970 23.680 ;
        RECT 20.330 23.440 20.980 23.670 ;
        RECT 20.330 23.420 20.970 23.440 ;
        RECT 18.025 22.490 19.305 22.510 ;
        RECT 17.980 22.260 19.350 22.490 ;
        RECT 18.025 22.250 19.305 22.260 ;
        RECT 20.330 21.310 20.970 21.325 ;
        RECT 20.330 21.080 20.980 21.310 ;
        RECT 20.330 21.065 20.970 21.080 ;
        RECT 18.025 20.130 19.305 20.150 ;
        RECT 17.980 19.900 19.350 20.130 ;
        RECT 18.025 19.890 19.305 19.900 ;
        RECT 20.330 18.950 20.970 18.965 ;
        RECT 20.330 18.720 20.980 18.950 ;
        RECT 20.330 18.705 20.970 18.720 ;
        RECT 18.025 17.770 19.305 17.790 ;
        RECT 17.980 17.540 19.350 17.770 ;
        RECT 18.025 17.530 19.305 17.540 ;
        RECT 21.490 17.295 21.780 28.725 ;
        RECT 27.355 28.390 27.995 28.405 ;
        RECT 27.355 28.160 28.005 28.390 ;
        RECT 27.355 28.145 27.995 28.160 ;
        RECT 25.050 27.210 26.330 27.230 ;
        RECT 25.005 26.980 26.375 27.210 ;
        RECT 25.050 26.970 26.330 26.980 ;
        RECT 27.355 26.030 27.995 26.040 ;
        RECT 27.355 25.800 28.005 26.030 ;
        RECT 27.355 25.780 27.995 25.800 ;
        RECT 25.050 24.850 26.330 24.870 ;
        RECT 25.005 24.620 26.375 24.850 ;
        RECT 25.050 24.610 26.330 24.620 ;
        RECT 27.355 23.670 27.995 23.680 ;
        RECT 27.355 23.440 28.005 23.670 ;
        RECT 27.355 23.420 27.995 23.440 ;
        RECT 25.050 22.490 26.330 22.510 ;
        RECT 25.005 22.260 26.375 22.490 ;
        RECT 25.050 22.250 26.330 22.260 ;
        RECT 27.355 21.310 27.995 21.325 ;
        RECT 27.355 21.080 28.005 21.310 ;
        RECT 27.355 21.065 27.995 21.080 ;
        RECT 25.050 20.130 26.330 20.150 ;
        RECT 25.005 19.900 26.375 20.130 ;
        RECT 25.050 19.890 26.330 19.900 ;
        RECT 27.355 18.950 27.995 18.965 ;
        RECT 27.355 18.720 28.005 18.950 ;
        RECT 27.355 18.705 27.995 18.720 ;
        RECT 25.050 17.770 26.330 17.790 ;
        RECT 25.005 17.540 26.375 17.770 ;
        RECT 25.050 17.530 26.330 17.540 ;
        RECT 28.515 17.295 28.805 28.725 ;
        RECT 35.090 28.390 35.730 28.405 ;
        RECT 35.090 28.160 35.740 28.390 ;
        RECT 35.090 28.145 35.730 28.160 ;
        RECT 32.785 27.210 34.065 27.230 ;
        RECT 32.740 26.980 34.110 27.210 ;
        RECT 32.785 26.970 34.065 26.980 ;
        RECT 35.090 26.030 35.730 26.040 ;
        RECT 35.090 25.800 35.740 26.030 ;
        RECT 35.090 25.780 35.730 25.800 ;
        RECT 32.785 24.850 34.065 24.870 ;
        RECT 32.740 24.620 34.110 24.850 ;
        RECT 32.785 24.610 34.065 24.620 ;
        RECT 35.090 23.670 35.730 23.680 ;
        RECT 35.090 23.440 35.740 23.670 ;
        RECT 35.090 23.420 35.730 23.440 ;
        RECT 32.785 22.490 34.065 22.510 ;
        RECT 32.740 22.260 34.110 22.490 ;
        RECT 32.785 22.250 34.065 22.260 ;
        RECT 35.090 21.310 35.730 21.325 ;
        RECT 35.090 21.080 35.740 21.310 ;
        RECT 35.090 21.065 35.730 21.080 ;
        RECT 32.785 20.130 34.065 20.150 ;
        RECT 32.740 19.900 34.110 20.130 ;
        RECT 32.785 19.890 34.065 19.900 ;
        RECT 35.090 18.950 35.730 18.965 ;
        RECT 35.090 18.720 35.740 18.950 ;
        RECT 35.090 18.705 35.730 18.720 ;
        RECT 32.785 17.770 34.065 17.790 ;
        RECT 32.740 17.540 34.110 17.770 ;
        RECT 32.785 17.530 34.065 17.540 ;
        RECT 36.250 17.295 36.540 28.725 ;
        RECT 42.645 28.390 43.285 28.405 ;
        RECT 42.645 28.160 43.295 28.390 ;
        RECT 42.645 28.145 43.285 28.160 ;
        RECT 40.340 27.210 41.620 27.230 ;
        RECT 40.295 26.980 41.665 27.210 ;
        RECT 40.340 26.970 41.620 26.980 ;
        RECT 42.645 26.030 43.285 26.040 ;
        RECT 42.645 25.800 43.295 26.030 ;
        RECT 42.645 25.780 43.285 25.800 ;
        RECT 40.340 24.850 41.620 24.870 ;
        RECT 40.295 24.620 41.665 24.850 ;
        RECT 40.340 24.610 41.620 24.620 ;
        RECT 42.645 23.670 43.285 23.680 ;
        RECT 42.645 23.440 43.295 23.670 ;
        RECT 42.645 23.420 43.285 23.440 ;
        RECT 40.340 22.490 41.620 22.510 ;
        RECT 40.295 22.260 41.665 22.490 ;
        RECT 40.340 22.250 41.620 22.260 ;
        RECT 42.645 21.310 43.285 21.325 ;
        RECT 42.645 21.080 43.295 21.310 ;
        RECT 42.645 21.065 43.285 21.080 ;
        RECT 40.340 20.130 41.620 20.150 ;
        RECT 40.295 19.900 41.665 20.130 ;
        RECT 40.340 19.890 41.620 19.900 ;
        RECT 42.645 18.950 43.285 18.965 ;
        RECT 42.645 18.720 43.295 18.950 ;
        RECT 42.645 18.705 43.285 18.720 ;
        RECT 40.340 17.770 41.620 17.790 ;
        RECT 40.295 17.540 41.665 17.770 ;
        RECT 40.340 17.530 41.620 17.540 ;
        RECT 43.805 17.295 44.095 28.725 ;
        RECT 50.455 28.390 51.095 28.405 ;
        RECT 50.455 28.160 51.105 28.390 ;
        RECT 50.455 28.145 51.095 28.160 ;
        RECT 48.150 27.210 49.430 27.230 ;
        RECT 48.105 26.980 49.475 27.210 ;
        RECT 48.150 26.970 49.430 26.980 ;
        RECT 50.455 26.030 51.095 26.040 ;
        RECT 50.455 25.800 51.105 26.030 ;
        RECT 50.455 25.780 51.095 25.800 ;
        RECT 48.150 24.850 49.430 24.870 ;
        RECT 48.105 24.620 49.475 24.850 ;
        RECT 48.150 24.610 49.430 24.620 ;
        RECT 50.455 23.670 51.095 23.680 ;
        RECT 50.455 23.440 51.105 23.670 ;
        RECT 50.455 23.420 51.095 23.440 ;
        RECT 48.150 22.490 49.430 22.510 ;
        RECT 48.105 22.260 49.475 22.490 ;
        RECT 48.150 22.250 49.430 22.260 ;
        RECT 50.455 21.310 51.095 21.325 ;
        RECT 50.455 21.080 51.105 21.310 ;
        RECT 50.455 21.065 51.095 21.080 ;
        RECT 48.150 20.130 49.430 20.150 ;
        RECT 48.105 19.900 49.475 20.130 ;
        RECT 48.150 19.890 49.430 19.900 ;
        RECT 50.455 18.950 51.095 18.965 ;
        RECT 50.455 18.720 51.105 18.950 ;
        RECT 50.455 18.705 51.095 18.720 ;
        RECT 48.150 17.770 49.430 17.790 ;
        RECT 48.105 17.540 49.475 17.770 ;
        RECT 48.150 17.530 49.430 17.540 ;
        RECT 51.615 17.295 51.905 28.725 ;
        RECT 57.965 28.390 58.605 28.405 ;
        RECT 57.965 28.160 58.615 28.390 ;
        RECT 57.965 28.145 58.605 28.160 ;
        RECT 55.660 27.210 56.940 27.230 ;
        RECT 55.615 26.980 56.985 27.210 ;
        RECT 55.660 26.970 56.940 26.980 ;
        RECT 57.965 26.030 58.605 26.040 ;
        RECT 57.965 25.800 58.615 26.030 ;
        RECT 57.965 25.780 58.605 25.800 ;
        RECT 55.660 24.850 56.940 24.870 ;
        RECT 55.615 24.620 56.985 24.850 ;
        RECT 55.660 24.610 56.940 24.620 ;
        RECT 57.965 23.670 58.605 23.680 ;
        RECT 57.965 23.440 58.615 23.670 ;
        RECT 57.965 23.420 58.605 23.440 ;
        RECT 55.660 22.490 56.940 22.510 ;
        RECT 55.615 22.260 56.985 22.490 ;
        RECT 55.660 22.250 56.940 22.260 ;
        RECT 57.965 21.310 58.605 21.325 ;
        RECT 57.965 21.080 58.615 21.310 ;
        RECT 57.965 21.065 58.605 21.080 ;
        RECT 55.660 20.130 56.940 20.150 ;
        RECT 55.615 19.900 56.985 20.130 ;
        RECT 55.660 19.890 56.940 19.900 ;
        RECT 57.965 18.950 58.605 18.965 ;
        RECT 57.965 18.720 58.615 18.950 ;
        RECT 57.965 18.705 58.605 18.720 ;
        RECT 55.660 17.770 56.940 17.790 ;
        RECT 55.615 17.540 56.985 17.770 ;
        RECT 55.660 17.530 56.940 17.540 ;
        RECT 59.125 17.295 59.415 28.725 ;
        RECT 65.640 28.390 66.280 28.405 ;
        RECT 65.640 28.160 66.290 28.390 ;
        RECT 65.640 28.145 66.280 28.160 ;
        RECT 63.335 27.210 64.615 27.230 ;
        RECT 63.290 26.980 64.660 27.210 ;
        RECT 63.335 26.970 64.615 26.980 ;
        RECT 65.640 26.030 66.280 26.040 ;
        RECT 65.640 25.800 66.290 26.030 ;
        RECT 65.640 25.780 66.280 25.800 ;
        RECT 63.335 24.850 64.615 24.870 ;
        RECT 63.290 24.620 64.660 24.850 ;
        RECT 63.335 24.610 64.615 24.620 ;
        RECT 65.640 23.670 66.280 23.680 ;
        RECT 65.640 23.440 66.290 23.670 ;
        RECT 65.640 23.420 66.280 23.440 ;
        RECT 63.335 22.490 64.615 22.510 ;
        RECT 63.290 22.260 64.660 22.490 ;
        RECT 63.335 22.250 64.615 22.260 ;
        RECT 65.640 21.310 66.280 21.325 ;
        RECT 65.640 21.080 66.290 21.310 ;
        RECT 65.640 21.065 66.280 21.080 ;
        RECT 63.335 20.130 64.615 20.150 ;
        RECT 63.290 19.900 64.660 20.130 ;
        RECT 63.335 19.890 64.615 19.900 ;
        RECT 65.640 18.950 66.280 18.965 ;
        RECT 65.640 18.720 66.290 18.950 ;
        RECT 65.640 18.705 66.280 18.720 ;
        RECT 63.335 17.770 64.615 17.790 ;
        RECT 63.290 17.540 64.660 17.770 ;
        RECT 63.335 17.530 64.615 17.540 ;
        RECT 66.800 17.295 67.090 28.725 ;
        RECT 73.150 28.390 73.790 28.405 ;
        RECT 73.150 28.160 73.800 28.390 ;
        RECT 73.150 28.145 73.790 28.160 ;
        RECT 70.845 27.210 72.125 27.230 ;
        RECT 70.800 26.980 72.170 27.210 ;
        RECT 70.845 26.970 72.125 26.980 ;
        RECT 73.150 26.030 73.790 26.040 ;
        RECT 73.150 25.800 73.800 26.030 ;
        RECT 73.150 25.780 73.790 25.800 ;
        RECT 70.845 24.850 72.125 24.870 ;
        RECT 70.800 24.620 72.170 24.850 ;
        RECT 70.845 24.610 72.125 24.620 ;
        RECT 73.150 23.670 73.790 23.680 ;
        RECT 73.150 23.440 73.800 23.670 ;
        RECT 73.150 23.420 73.790 23.440 ;
        RECT 70.845 22.490 72.125 22.510 ;
        RECT 70.800 22.260 72.170 22.490 ;
        RECT 70.845 22.250 72.125 22.260 ;
        RECT 73.150 21.310 73.790 21.325 ;
        RECT 73.150 21.080 73.800 21.310 ;
        RECT 73.150 21.065 73.790 21.080 ;
        RECT 70.845 20.130 72.125 20.150 ;
        RECT 70.800 19.900 72.170 20.130 ;
        RECT 70.845 19.890 72.125 19.900 ;
        RECT 73.150 18.950 73.790 18.965 ;
        RECT 73.150 18.720 73.800 18.950 ;
        RECT 73.150 18.705 73.790 18.720 ;
        RECT 70.845 17.770 72.125 17.790 ;
        RECT 70.800 17.540 72.170 17.770 ;
        RECT 70.845 17.530 72.125 17.540 ;
        RECT 74.310 17.295 74.600 28.725 ;
        RECT 80.845 28.455 81.135 28.745 ;
        RECT 80.920 25.225 81.060 28.455 ;
        RECT 80.845 24.935 81.135 25.225 ;
        RECT 80.845 23.400 81.135 23.690 ;
        RECT 80.920 20.170 81.060 23.400 ;
        RECT 80.845 19.880 81.135 20.170 ;
        RECT 80.845 18.345 81.135 18.635 ;
        RECT 11.530 16.915 74.605 17.295 ;
        RECT 10.385 16.590 11.025 16.600 ;
        RECT 10.385 16.360 11.035 16.590 ;
        RECT 10.385 16.340 11.025 16.360 ;
        RECT 8.080 15.410 9.360 15.430 ;
        RECT 8.035 15.180 9.405 15.410 ;
        RECT 8.080 15.170 9.360 15.180 ;
        RECT 10.385 14.230 11.025 14.240 ;
        RECT 10.385 14.000 11.035 14.230 ;
        RECT 10.385 13.980 11.025 14.000 ;
        RECT 8.080 13.050 9.360 13.070 ;
        RECT 8.035 12.820 9.405 13.050 ;
        RECT 8.080 12.810 9.360 12.820 ;
        RECT 11.545 12.320 11.835 16.915 ;
        RECT 14.870 16.590 15.510 16.600 ;
        RECT 14.870 16.360 15.520 16.590 ;
        RECT 14.870 16.340 15.510 16.360 ;
        RECT 12.565 15.410 13.845 15.430 ;
        RECT 12.520 15.180 13.890 15.410 ;
        RECT 12.565 15.170 13.845 15.180 ;
        RECT 14.870 14.230 15.510 14.240 ;
        RECT 14.870 14.000 15.520 14.230 ;
        RECT 14.870 13.980 15.510 14.000 ;
        RECT 12.565 13.050 13.845 13.070 ;
        RECT 12.520 12.820 13.890 13.050 ;
        RECT 12.565 12.810 13.845 12.820 ;
        RECT 16.030 12.320 16.320 16.915 ;
        RECT 20.330 16.590 20.970 16.600 ;
        RECT 20.330 16.360 20.980 16.590 ;
        RECT 20.330 16.340 20.970 16.360 ;
        RECT 18.025 15.410 19.305 15.430 ;
        RECT 17.980 15.180 19.350 15.410 ;
        RECT 18.025 15.170 19.305 15.180 ;
        RECT 20.330 14.230 20.970 14.240 ;
        RECT 20.330 14.000 20.980 14.230 ;
        RECT 20.330 13.980 20.970 14.000 ;
        RECT 18.025 13.050 19.305 13.070 ;
        RECT 17.980 12.820 19.350 13.050 ;
        RECT 18.025 12.810 19.305 12.820 ;
        RECT 21.490 12.320 21.780 16.915 ;
        RECT 27.355 16.590 27.995 16.600 ;
        RECT 27.355 16.360 28.005 16.590 ;
        RECT 27.355 16.340 27.995 16.360 ;
        RECT 25.050 15.410 26.330 15.430 ;
        RECT 25.005 15.180 26.375 15.410 ;
        RECT 25.050 15.170 26.330 15.180 ;
        RECT 27.355 14.230 27.995 14.240 ;
        RECT 27.355 14.000 28.005 14.230 ;
        RECT 27.355 13.980 27.995 14.000 ;
        RECT 25.050 13.050 26.330 13.070 ;
        RECT 25.005 12.820 26.375 13.050 ;
        RECT 25.050 12.810 26.330 12.820 ;
        RECT 28.515 12.320 28.805 16.915 ;
        RECT 35.090 16.590 35.730 16.600 ;
        RECT 35.090 16.360 35.740 16.590 ;
        RECT 35.090 16.340 35.730 16.360 ;
        RECT 32.785 15.410 34.065 15.430 ;
        RECT 32.740 15.180 34.110 15.410 ;
        RECT 32.785 15.170 34.065 15.180 ;
        RECT 35.090 14.230 35.730 14.240 ;
        RECT 35.090 14.000 35.740 14.230 ;
        RECT 35.090 13.980 35.730 14.000 ;
        RECT 32.785 13.050 34.065 13.070 ;
        RECT 32.740 12.820 34.110 13.050 ;
        RECT 32.785 12.810 34.065 12.820 ;
        RECT 36.250 12.320 36.540 16.915 ;
        RECT 42.645 16.590 43.285 16.600 ;
        RECT 42.645 16.360 43.295 16.590 ;
        RECT 42.645 16.340 43.285 16.360 ;
        RECT 40.340 15.410 41.620 15.430 ;
        RECT 40.295 15.180 41.665 15.410 ;
        RECT 40.340 15.170 41.620 15.180 ;
        RECT 42.645 14.230 43.285 14.240 ;
        RECT 42.645 14.000 43.295 14.230 ;
        RECT 42.645 13.980 43.285 14.000 ;
        RECT 40.340 13.050 41.620 13.070 ;
        RECT 40.295 12.820 41.665 13.050 ;
        RECT 40.340 12.810 41.620 12.820 ;
        RECT 43.805 12.320 44.095 16.915 ;
        RECT 50.455 16.590 51.095 16.600 ;
        RECT 50.455 16.360 51.105 16.590 ;
        RECT 50.455 16.340 51.095 16.360 ;
        RECT 48.150 15.410 49.430 15.430 ;
        RECT 48.105 15.180 49.475 15.410 ;
        RECT 48.150 15.170 49.430 15.180 ;
        RECT 50.455 14.230 51.095 14.240 ;
        RECT 50.455 14.000 51.105 14.230 ;
        RECT 50.455 13.980 51.095 14.000 ;
        RECT 48.150 13.050 49.430 13.070 ;
        RECT 48.105 12.820 49.475 13.050 ;
        RECT 48.150 12.810 49.430 12.820 ;
        RECT 51.615 12.320 51.905 16.915 ;
        RECT 57.965 16.590 58.605 16.600 ;
        RECT 57.965 16.360 58.615 16.590 ;
        RECT 57.965 16.340 58.605 16.360 ;
        RECT 55.660 15.410 56.940 15.430 ;
        RECT 55.615 15.180 56.985 15.410 ;
        RECT 55.660 15.170 56.940 15.180 ;
        RECT 57.965 14.230 58.605 14.240 ;
        RECT 57.965 14.000 58.615 14.230 ;
        RECT 57.965 13.980 58.605 14.000 ;
        RECT 55.660 13.050 56.940 13.070 ;
        RECT 55.615 12.820 56.985 13.050 ;
        RECT 55.660 12.810 56.940 12.820 ;
        RECT 59.125 12.320 59.415 16.915 ;
        RECT 65.640 16.590 66.280 16.600 ;
        RECT 65.640 16.360 66.290 16.590 ;
        RECT 65.640 16.340 66.280 16.360 ;
        RECT 63.335 15.410 64.615 15.430 ;
        RECT 63.290 15.180 64.660 15.410 ;
        RECT 63.335 15.170 64.615 15.180 ;
        RECT 65.640 14.230 66.280 14.240 ;
        RECT 65.640 14.000 66.290 14.230 ;
        RECT 65.640 13.980 66.280 14.000 ;
        RECT 63.335 13.050 64.615 13.070 ;
        RECT 63.290 12.820 64.660 13.050 ;
        RECT 63.335 12.810 64.615 12.820 ;
        RECT 66.800 12.320 67.090 16.915 ;
        RECT 73.150 16.590 73.790 16.600 ;
        RECT 73.150 16.360 73.800 16.590 ;
        RECT 73.150 16.340 73.790 16.360 ;
        RECT 70.845 15.410 72.125 15.430 ;
        RECT 70.800 15.180 72.170 15.410 ;
        RECT 70.845 15.170 72.125 15.180 ;
        RECT 73.150 14.230 73.790 14.240 ;
        RECT 73.150 14.000 73.800 14.230 ;
        RECT 73.150 13.980 73.790 14.000 ;
        RECT 70.845 13.050 72.125 13.070 ;
        RECT 70.800 12.820 72.170 13.050 ;
        RECT 70.845 12.810 72.125 12.820 ;
        RECT 74.310 12.320 74.600 16.915 ;
        RECT 80.920 15.115 81.060 18.345 ;
        RECT 80.845 14.825 81.135 15.115 ;
        RECT 80.845 13.505 81.135 13.580 ;
        RECT 83.550 13.505 83.745 45.155 ;
        RECT 86.395 43.620 86.685 43.910 ;
        RECT 86.470 40.390 86.610 43.620 ;
        RECT 86.385 40.090 86.685 40.390 ;
        RECT 86.395 38.565 86.685 38.855 ;
        RECT 86.470 35.335 86.610 38.565 ;
        RECT 86.395 35.045 86.685 35.335 ;
        RECT 86.395 33.510 86.685 33.800 ;
        RECT 86.470 30.280 86.610 33.510 ;
        RECT 86.395 29.990 86.685 30.280 ;
        RECT 86.395 28.455 86.685 28.745 ;
        RECT 86.470 25.225 86.610 28.455 ;
        RECT 86.395 24.935 86.685 25.225 ;
        RECT 86.395 23.400 86.685 23.690 ;
        RECT 86.470 20.170 86.610 23.400 ;
        RECT 86.395 19.880 86.685 20.170 ;
        RECT 92.065 20.160 92.355 20.170 ;
        RECT 89.100 19.895 92.760 20.160 ;
        RECT 86.395 18.345 86.685 18.635 ;
        RECT 86.470 15.115 86.610 18.345 ;
        RECT 86.395 14.825 86.685 15.115 ;
        RECT 80.845 13.365 83.745 13.505 ;
        RECT 86.395 13.505 86.685 13.580 ;
        RECT 89.100 13.505 89.295 19.895 ;
        RECT 92.065 19.880 92.355 19.895 ;
        RECT 92.065 18.345 92.355 18.635 ;
        RECT 92.140 15.115 92.280 18.345 ;
        RECT 92.065 14.825 92.355 15.115 ;
        RECT 86.395 13.365 89.295 13.505 ;
        RECT 80.845 13.290 81.135 13.365 ;
        RECT 86.395 13.290 86.685 13.365 ;
        RECT 10.385 11.870 11.025 11.880 ;
        RECT 14.870 11.870 15.510 11.880 ;
        RECT 20.330 11.870 20.970 11.880 ;
        RECT 27.355 11.870 27.995 11.880 ;
        RECT 35.090 11.870 35.730 11.880 ;
        RECT 42.645 11.870 43.285 11.880 ;
        RECT 50.455 11.870 51.095 11.880 ;
        RECT 57.965 11.870 58.605 11.880 ;
        RECT 65.640 11.870 66.280 11.880 ;
        RECT 73.150 11.870 73.790 11.880 ;
        RECT 10.385 11.640 11.035 11.870 ;
        RECT 14.870 11.640 15.520 11.870 ;
        RECT 20.330 11.640 20.980 11.870 ;
        RECT 27.355 11.640 28.005 11.870 ;
        RECT 35.090 11.640 35.740 11.870 ;
        RECT 42.645 11.640 43.295 11.870 ;
        RECT 50.455 11.640 51.105 11.870 ;
        RECT 57.965 11.640 58.615 11.870 ;
        RECT 65.640 11.640 66.290 11.870 ;
        RECT 73.150 11.640 73.800 11.870 ;
        RECT 10.385 11.620 11.025 11.640 ;
        RECT 14.870 11.620 15.510 11.640 ;
        RECT 20.330 11.620 20.970 11.640 ;
        RECT 27.355 11.620 27.995 11.640 ;
        RECT 35.090 11.620 35.730 11.640 ;
        RECT 42.645 11.620 43.285 11.640 ;
        RECT 50.455 11.620 51.095 11.640 ;
        RECT 57.965 11.620 58.605 11.640 ;
        RECT 65.640 11.620 66.280 11.640 ;
        RECT 73.150 11.620 73.790 11.640 ;
      LAYER met2 ;
        RECT 8.080 12.810 9.360 48.820 ;
        RECT 10.385 11.760 11.035 47.305 ;
        RECT 12.565 12.810 13.845 48.785 ;
        RECT 14.870 11.760 15.520 47.305 ;
        RECT 18.025 12.810 19.305 48.785 ;
        RECT 20.330 11.760 20.980 47.305 ;
        RECT 25.050 12.810 26.330 48.785 ;
        RECT 27.355 11.760 28.005 47.305 ;
        RECT 32.785 12.810 34.065 48.785 ;
        RECT 35.090 11.760 35.740 47.305 ;
        RECT 40.340 12.810 41.620 48.785 ;
        RECT 42.645 11.760 43.295 47.305 ;
        RECT 48.150 12.810 49.430 48.785 ;
        RECT 50.455 11.760 51.105 47.305 ;
        RECT 55.660 12.810 56.940 48.785 ;
        RECT 57.965 11.760 58.615 47.305 ;
        RECT 63.335 12.810 64.615 48.785 ;
        RECT 65.640 11.760 66.290 47.305 ;
        RECT 70.845 12.810 72.125 48.785 ;
        RECT 73.150 11.760 73.800 47.305 ;
        RECT 10.385 11.620 11.025 11.760 ;
        RECT 14.870 11.620 15.510 11.760 ;
        RECT 20.330 11.620 20.970 11.760 ;
        RECT 27.355 11.620 27.995 11.760 ;
        RECT 35.090 11.620 35.730 11.760 ;
        RECT 42.645 11.620 43.285 11.760 ;
        RECT 50.455 11.620 51.095 11.760 ;
        RECT 57.965 11.620 58.605 11.760 ;
        RECT 65.640 11.620 66.280 11.760 ;
        RECT 73.150 11.620 73.790 11.760 ;
  END
END vref_gen_nmos_with_trim
END LIBRARY

